VERSION 5.7 ;
BUSBITCHARS "[]" ;
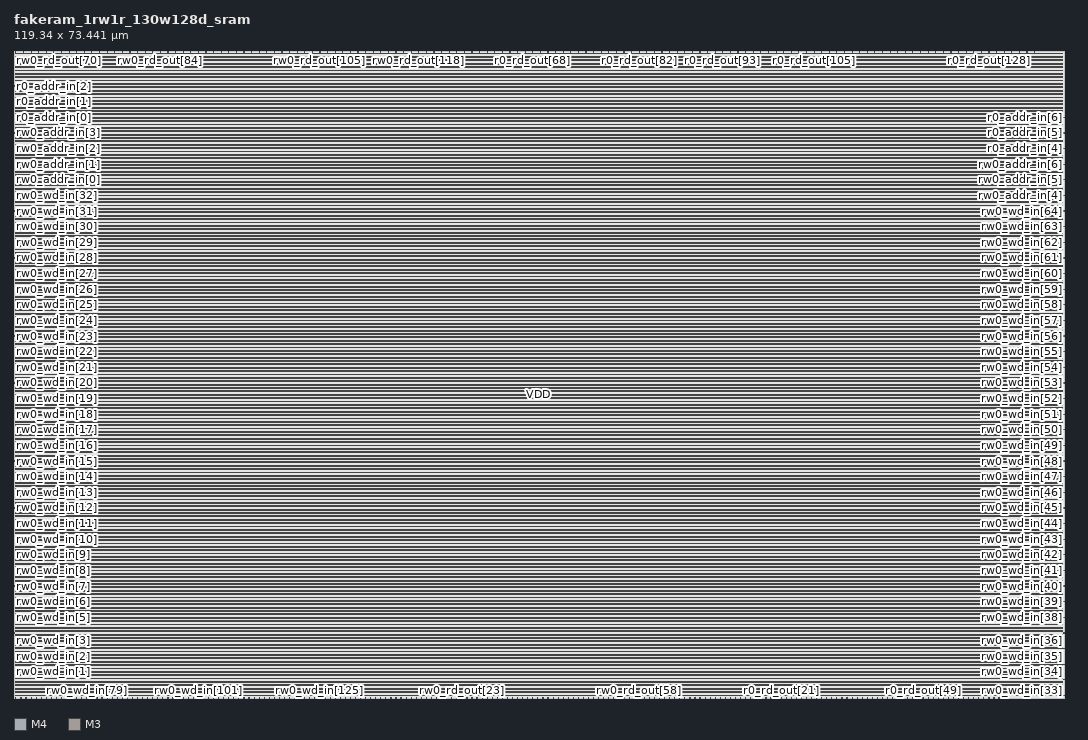
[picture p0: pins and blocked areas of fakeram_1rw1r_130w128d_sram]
MACRO fakeram_1rw1r_130w128d_sram
  FOREIGN fakeram_1rw1r_130w128d_sram 0 0 ;
  SYMMETRY X Y R90 ;
  SIZE 119.340 BY 73.441 ;
  CLASS BLOCK ;
  PIN rw0_wd_in[0]
    DIRECTION INPUT ;
    USE SIGNAL ;
    SHAPE ABUTMENT ;
    PORT
      LAYER M4 ;
      RECT 0.000 0.276 0.072 0.300 ;
    END
  END rw0_wd_in[0]
  PIN rw0_wd_in[1]
    DIRECTION INPUT ;
    USE SIGNAL ;
    SHAPE ABUTMENT ;
    PORT
      LAYER M4 ;
      RECT 0.000 2.052 0.072 2.076 ;
    END
  END rw0_wd_in[1]
  PIN rw0_wd_in[2]
    DIRECTION INPUT ;
    USE SIGNAL ;
    SHAPE ABUTMENT ;
    PORT
      LAYER M4 ;
      RECT 0.000 3.828 0.072 3.852 ;
    END
  END rw0_wd_in[2]
  PIN rw0_wd_in[3]
    DIRECTION INPUT ;
    USE SIGNAL ;
    SHAPE ABUTMENT ;
    PORT
      LAYER M4 ;
      RECT 0.000 5.604 0.072 5.628 ;
    END
  END rw0_wd_in[3]
  PIN rw0_wd_in[4]
    DIRECTION INPUT ;
    USE SIGNAL ;
    SHAPE ABUTMENT ;
    PORT
      LAYER M4 ;
      RECT 0.000 7.380 0.072 7.404 ;
    END
  END rw0_wd_in[4]
  PIN rw0_wd_in[5]
    DIRECTION INPUT ;
    USE SIGNAL ;
    SHAPE ABUTMENT ;
    PORT
      LAYER M4 ;
      RECT 0.000 9.156 0.072 9.180 ;
    END
  END rw0_wd_in[5]
  PIN rw0_wd_in[6]
    DIRECTION INPUT ;
    USE SIGNAL ;
    SHAPE ABUTMENT ;
    PORT
      LAYER M4 ;
      RECT 0.000 10.932 0.072 10.956 ;
    END
  END rw0_wd_in[6]
  PIN rw0_wd_in[7]
    DIRECTION INPUT ;
    USE SIGNAL ;
    SHAPE ABUTMENT ;
    PORT
      LAYER M4 ;
      RECT 0.000 12.708 0.072 12.732 ;
    END
  END rw0_wd_in[7]
  PIN rw0_wd_in[8]
    DIRECTION INPUT ;
    USE SIGNAL ;
    SHAPE ABUTMENT ;
    PORT
      LAYER M4 ;
      RECT 0.000 14.484 0.072 14.508 ;
    END
  END rw0_wd_in[8]
  PIN rw0_wd_in[9]
    DIRECTION INPUT ;
    USE SIGNAL ;
    SHAPE ABUTMENT ;
    PORT
      LAYER M4 ;
      RECT 0.000 16.260 0.072 16.284 ;
    END
  END rw0_wd_in[9]
  PIN rw0_wd_in[10]
    DIRECTION INPUT ;
    USE SIGNAL ;
    SHAPE ABUTMENT ;
    PORT
      LAYER M4 ;
      RECT 0.000 18.036 0.072 18.060 ;
    END
  END rw0_wd_in[10]
  PIN rw0_wd_in[11]
    DIRECTION INPUT ;
    USE SIGNAL ;
    SHAPE ABUTMENT ;
    PORT
      LAYER M4 ;
      RECT 0.000 19.812 0.072 19.836 ;
    END
  END rw0_wd_in[11]
  PIN rw0_wd_in[12]
    DIRECTION INPUT ;
    USE SIGNAL ;
    SHAPE ABUTMENT ;
    PORT
      LAYER M4 ;
      RECT 0.000 21.588 0.072 21.612 ;
    END
  END rw0_wd_in[12]
  PIN rw0_wd_in[13]
    DIRECTION INPUT ;
    USE SIGNAL ;
    SHAPE ABUTMENT ;
    PORT
      LAYER M4 ;
      RECT 0.000 23.364 0.072 23.388 ;
    END
  END rw0_wd_in[13]
  PIN rw0_wd_in[14]
    DIRECTION INPUT ;
    USE SIGNAL ;
    SHAPE ABUTMENT ;
    PORT
      LAYER M4 ;
      RECT 0.000 25.140 0.072 25.164 ;
    END
  END rw0_wd_in[14]
  PIN rw0_wd_in[15]
    DIRECTION INPUT ;
    USE SIGNAL ;
    SHAPE ABUTMENT ;
    PORT
      LAYER M4 ;
      RECT 0.000 26.916 0.072 26.940 ;
    END
  END rw0_wd_in[15]
  PIN rw0_wd_in[16]
    DIRECTION INPUT ;
    USE SIGNAL ;
    SHAPE ABUTMENT ;
    PORT
      LAYER M4 ;
      RECT 0.000 28.692 0.072 28.716 ;
    END
  END rw0_wd_in[16]
  PIN rw0_wd_in[17]
    DIRECTION INPUT ;
    USE SIGNAL ;
    SHAPE ABUTMENT ;
    PORT
      LAYER M4 ;
      RECT 0.000 30.468 0.072 30.492 ;
    END
  END rw0_wd_in[17]
  PIN rw0_wd_in[18]
    DIRECTION INPUT ;
    USE SIGNAL ;
    SHAPE ABUTMENT ;
    PORT
      LAYER M4 ;
      RECT 0.000 32.244 0.072 32.268 ;
    END
  END rw0_wd_in[18]
  PIN rw0_wd_in[19]
    DIRECTION INPUT ;
    USE SIGNAL ;
    SHAPE ABUTMENT ;
    PORT
      LAYER M4 ;
      RECT 0.000 34.020 0.072 34.044 ;
    END
  END rw0_wd_in[19]
  PIN rw0_wd_in[20]
    DIRECTION INPUT ;
    USE SIGNAL ;
    SHAPE ABUTMENT ;
    PORT
      LAYER M4 ;
      RECT 0.000 35.796 0.072 35.820 ;
    END
  END rw0_wd_in[20]
  PIN rw0_wd_in[21]
    DIRECTION INPUT ;
    USE SIGNAL ;
    SHAPE ABUTMENT ;
    PORT
      LAYER M4 ;
      RECT 0.000 37.572 0.072 37.596 ;
    END
  END rw0_wd_in[21]
  PIN rw0_wd_in[22]
    DIRECTION INPUT ;
    USE SIGNAL ;
    SHAPE ABUTMENT ;
    PORT
      LAYER M4 ;
      RECT 0.000 39.348 0.072 39.372 ;
    END
  END rw0_wd_in[22]
  PIN rw0_wd_in[23]
    DIRECTION INPUT ;
    USE SIGNAL ;
    SHAPE ABUTMENT ;
    PORT
      LAYER M4 ;
      RECT 0.000 41.124 0.072 41.148 ;
    END
  END rw0_wd_in[23]
  PIN rw0_wd_in[24]
    DIRECTION INPUT ;
    USE SIGNAL ;
    SHAPE ABUTMENT ;
    PORT
      LAYER M4 ;
      RECT 0.000 42.900 0.072 42.924 ;
    END
  END rw0_wd_in[24]
  PIN rw0_wd_in[25]
    DIRECTION INPUT ;
    USE SIGNAL ;
    SHAPE ABUTMENT ;
    PORT
      LAYER M4 ;
      RECT 0.000 44.676 0.072 44.700 ;
    END
  END rw0_wd_in[25]
  PIN rw0_wd_in[26]
    DIRECTION INPUT ;
    USE SIGNAL ;
    SHAPE ABUTMENT ;
    PORT
      LAYER M4 ;
      RECT 0.000 46.452 0.072 46.476 ;
    END
  END rw0_wd_in[26]
  PIN rw0_wd_in[27]
    DIRECTION INPUT ;
    USE SIGNAL ;
    SHAPE ABUTMENT ;
    PORT
      LAYER M4 ;
      RECT 0.000 48.228 0.072 48.252 ;
    END
  END rw0_wd_in[27]
  PIN rw0_wd_in[28]
    DIRECTION INPUT ;
    USE SIGNAL ;
    SHAPE ABUTMENT ;
    PORT
      LAYER M4 ;
      RECT 0.000 50.004 0.072 50.028 ;
    END
  END rw0_wd_in[28]
  PIN rw0_wd_in[29]
    DIRECTION INPUT ;
    USE SIGNAL ;
    SHAPE ABUTMENT ;
    PORT
      LAYER M4 ;
      RECT 0.000 51.780 0.072 51.804 ;
    END
  END rw0_wd_in[29]
  PIN rw0_wd_in[30]
    DIRECTION INPUT ;
    USE SIGNAL ;
    SHAPE ABUTMENT ;
    PORT
      LAYER M4 ;
      RECT 0.000 53.556 0.072 53.580 ;
    END
  END rw0_wd_in[30]
  PIN rw0_wd_in[31]
    DIRECTION INPUT ;
    USE SIGNAL ;
    SHAPE ABUTMENT ;
    PORT
      LAYER M4 ;
      RECT 0.000 55.332 0.072 55.356 ;
    END
  END rw0_wd_in[31]
  PIN rw0_wd_in[32]
    DIRECTION INPUT ;
    USE SIGNAL ;
    SHAPE ABUTMENT ;
    PORT
      LAYER M4 ;
      RECT 0.000 57.108 0.072 57.132 ;
    END
  END rw0_wd_in[32]
  PIN rw0_wd_in[33]
    DIRECTION INPUT ;
    USE SIGNAL ;
    SHAPE ABUTMENT ;
    PORT
      LAYER M4 ;
      RECT 119.268 0.276 119.340 0.300 ;
    END
  END rw0_wd_in[33]
  PIN rw0_wd_in[34]
    DIRECTION INPUT ;
    USE SIGNAL ;
    SHAPE ABUTMENT ;
    PORT
      LAYER M4 ;
      RECT 119.268 2.052 119.340 2.076 ;
    END
  END rw0_wd_in[34]
  PIN rw0_wd_in[35]
    DIRECTION INPUT ;
    USE SIGNAL ;
    SHAPE ABUTMENT ;
    PORT
      LAYER M4 ;
      RECT 119.268 3.828 119.340 3.852 ;
    END
  END rw0_wd_in[35]
  PIN rw0_wd_in[36]
    DIRECTION INPUT ;
    USE SIGNAL ;
    SHAPE ABUTMENT ;
    PORT
      LAYER M4 ;
      RECT 119.268 5.604 119.340 5.628 ;
    END
  END rw0_wd_in[36]
  PIN rw0_wd_in[37]
    DIRECTION INPUT ;
    USE SIGNAL ;
    SHAPE ABUTMENT ;
    PORT
      LAYER M4 ;
      RECT 119.268 7.380 119.340 7.404 ;
    END
  END rw0_wd_in[37]
  PIN rw0_wd_in[38]
    DIRECTION INPUT ;
    USE SIGNAL ;
    SHAPE ABUTMENT ;
    PORT
      LAYER M4 ;
      RECT 119.268 9.156 119.340 9.180 ;
    END
  END rw0_wd_in[38]
  PIN rw0_wd_in[39]
    DIRECTION INPUT ;
    USE SIGNAL ;
    SHAPE ABUTMENT ;
    PORT
      LAYER M4 ;
      RECT 119.268 10.932 119.340 10.956 ;
    END
  END rw0_wd_in[39]
  PIN rw0_wd_in[40]
    DIRECTION INPUT ;
    USE SIGNAL ;
    SHAPE ABUTMENT ;
    PORT
      LAYER M4 ;
      RECT 119.268 12.708 119.340 12.732 ;
    END
  END rw0_wd_in[40]
  PIN rw0_wd_in[41]
    DIRECTION INPUT ;
    USE SIGNAL ;
    SHAPE ABUTMENT ;
    PORT
      LAYER M4 ;
      RECT 119.268 14.484 119.340 14.508 ;
    END
  END rw0_wd_in[41]
  PIN rw0_wd_in[42]
    DIRECTION INPUT ;
    USE SIGNAL ;
    SHAPE ABUTMENT ;
    PORT
      LAYER M4 ;
      RECT 119.268 16.260 119.340 16.284 ;
    END
  END rw0_wd_in[42]
  PIN rw0_wd_in[43]
    DIRECTION INPUT ;
    USE SIGNAL ;
    SHAPE ABUTMENT ;
    PORT
      LAYER M4 ;
      RECT 119.268 18.036 119.340 18.060 ;
    END
  END rw0_wd_in[43]
  PIN rw0_wd_in[44]
    DIRECTION INPUT ;
    USE SIGNAL ;
    SHAPE ABUTMENT ;
    PORT
      LAYER M4 ;
      RECT 119.268 19.812 119.340 19.836 ;
    END
  END rw0_wd_in[44]
  PIN rw0_wd_in[45]
    DIRECTION INPUT ;
    USE SIGNAL ;
    SHAPE ABUTMENT ;
    PORT
      LAYER M4 ;
      RECT 119.268 21.588 119.340 21.612 ;
    END
  END rw0_wd_in[45]
  PIN rw0_wd_in[46]
    DIRECTION INPUT ;
    USE SIGNAL ;
    SHAPE ABUTMENT ;
    PORT
      LAYER M4 ;
      RECT 119.268 23.364 119.340 23.388 ;
    END
  END rw0_wd_in[46]
  PIN rw0_wd_in[47]
    DIRECTION INPUT ;
    USE SIGNAL ;
    SHAPE ABUTMENT ;
    PORT
      LAYER M4 ;
      RECT 119.268 25.140 119.340 25.164 ;
    END
  END rw0_wd_in[47]
  PIN rw0_wd_in[48]
    DIRECTION INPUT ;
    USE SIGNAL ;
    SHAPE ABUTMENT ;
    PORT
      LAYER M4 ;
      RECT 119.268 26.916 119.340 26.940 ;
    END
  END rw0_wd_in[48]
  PIN rw0_wd_in[49]
    DIRECTION INPUT ;
    USE SIGNAL ;
    SHAPE ABUTMENT ;
    PORT
      LAYER M4 ;
      RECT 119.268 28.692 119.340 28.716 ;
    END
  END rw0_wd_in[49]
  PIN rw0_wd_in[50]
    DIRECTION INPUT ;
    USE SIGNAL ;
    SHAPE ABUTMENT ;
    PORT
      LAYER M4 ;
      RECT 119.268 30.468 119.340 30.492 ;
    END
  END rw0_wd_in[50]
  PIN rw0_wd_in[51]
    DIRECTION INPUT ;
    USE SIGNAL ;
    SHAPE ABUTMENT ;
    PORT
      LAYER M4 ;
      RECT 119.268 32.244 119.340 32.268 ;
    END
  END rw0_wd_in[51]
  PIN rw0_wd_in[52]
    DIRECTION INPUT ;
    USE SIGNAL ;
    SHAPE ABUTMENT ;
    PORT
      LAYER M4 ;
      RECT 119.268 34.020 119.340 34.044 ;
    END
  END rw0_wd_in[52]
  PIN rw0_wd_in[53]
    DIRECTION INPUT ;
    USE SIGNAL ;
    SHAPE ABUTMENT ;
    PORT
      LAYER M4 ;
      RECT 119.268 35.796 119.340 35.820 ;
    END
  END rw0_wd_in[53]
  PIN rw0_wd_in[54]
    DIRECTION INPUT ;
    USE SIGNAL ;
    SHAPE ABUTMENT ;
    PORT
      LAYER M4 ;
      RECT 119.268 37.572 119.340 37.596 ;
    END
  END rw0_wd_in[54]
  PIN rw0_wd_in[55]
    DIRECTION INPUT ;
    USE SIGNAL ;
    SHAPE ABUTMENT ;
    PORT
      LAYER M4 ;
      RECT 119.268 39.348 119.340 39.372 ;
    END
  END rw0_wd_in[55]
  PIN rw0_wd_in[56]
    DIRECTION INPUT ;
    USE SIGNAL ;
    SHAPE ABUTMENT ;
    PORT
      LAYER M4 ;
      RECT 119.268 41.124 119.340 41.148 ;
    END
  END rw0_wd_in[56]
  PIN rw0_wd_in[57]
    DIRECTION INPUT ;
    USE SIGNAL ;
    SHAPE ABUTMENT ;
    PORT
      LAYER M4 ;
      RECT 119.268 42.900 119.340 42.924 ;
    END
  END rw0_wd_in[57]
  PIN rw0_wd_in[58]
    DIRECTION INPUT ;
    USE SIGNAL ;
    SHAPE ABUTMENT ;
    PORT
      LAYER M4 ;
      RECT 119.268 44.676 119.340 44.700 ;
    END
  END rw0_wd_in[58]
  PIN rw0_wd_in[59]
    DIRECTION INPUT ;
    USE SIGNAL ;
    SHAPE ABUTMENT ;
    PORT
      LAYER M4 ;
      RECT 119.268 46.452 119.340 46.476 ;
    END
  END rw0_wd_in[59]
  PIN rw0_wd_in[60]
    DIRECTION INPUT ;
    USE SIGNAL ;
    SHAPE ABUTMENT ;
    PORT
      LAYER M4 ;
      RECT 119.268 48.228 119.340 48.252 ;
    END
  END rw0_wd_in[60]
  PIN rw0_wd_in[61]
    DIRECTION INPUT ;
    USE SIGNAL ;
    SHAPE ABUTMENT ;
    PORT
      LAYER M4 ;
      RECT 119.268 50.004 119.340 50.028 ;
    END
  END rw0_wd_in[61]
  PIN rw0_wd_in[62]
    DIRECTION INPUT ;
    USE SIGNAL ;
    SHAPE ABUTMENT ;
    PORT
      LAYER M4 ;
      RECT 119.268 51.780 119.340 51.804 ;
    END
  END rw0_wd_in[62]
  PIN rw0_wd_in[63]
    DIRECTION INPUT ;
    USE SIGNAL ;
    SHAPE ABUTMENT ;
    PORT
      LAYER M4 ;
      RECT 119.268 53.556 119.340 53.580 ;
    END
  END rw0_wd_in[63]
  PIN rw0_wd_in[64]
    DIRECTION INPUT ;
    USE SIGNAL ;
    SHAPE ABUTMENT ;
    PORT
      LAYER M4 ;
      RECT 119.268 55.332 119.340 55.356 ;
    END
  END rw0_wd_in[64]
  PIN rw0_wd_in[65]
    DIRECTION INPUT ;
    USE SIGNAL ;
    SHAPE ABUTMENT ;
    PORT
      LAYER M3 ;
      RECT 0.207 0.000 0.225 0.054 ;
    END
  END rw0_wd_in[65]
  PIN rw0_wd_in[66]
    DIRECTION INPUT ;
    USE SIGNAL ;
    SHAPE ABUTMENT ;
    PORT
      LAYER M3 ;
      RECT 0.783 0.000 0.801 0.054 ;
    END
  END rw0_wd_in[66]
  PIN rw0_wd_in[67]
    DIRECTION INPUT ;
    USE SIGNAL ;
    SHAPE ABUTMENT ;
    PORT
      LAYER M3 ;
      RECT 1.359 0.000 1.377 0.054 ;
    END
  END rw0_wd_in[67]
  PIN rw0_wd_in[68]
    DIRECTION INPUT ;
    USE SIGNAL ;
    SHAPE ABUTMENT ;
    PORT
      LAYER M3 ;
      RECT 1.935 0.000 1.953 0.054 ;
    END
  END rw0_wd_in[68]
  PIN rw0_wd_in[69]
    DIRECTION INPUT ;
    USE SIGNAL ;
    SHAPE ABUTMENT ;
    PORT
      LAYER M3 ;
      RECT 2.511 0.000 2.529 0.054 ;
    END
  END rw0_wd_in[69]
  PIN rw0_wd_in[70]
    DIRECTION INPUT ;
    USE SIGNAL ;
    SHAPE ABUTMENT ;
    PORT
      LAYER M3 ;
      RECT 3.087 0.000 3.105 0.054 ;
    END
  END rw0_wd_in[70]
  PIN rw0_wd_in[71]
    DIRECTION INPUT ;
    USE SIGNAL ;
    SHAPE ABUTMENT ;
    PORT
      LAYER M3 ;
      RECT 3.663 0.000 3.681 0.054 ;
    END
  END rw0_wd_in[71]
  PIN rw0_wd_in[72]
    DIRECTION INPUT ;
    USE SIGNAL ;
    SHAPE ABUTMENT ;
    PORT
      LAYER M3 ;
      RECT 4.239 0.000 4.257 0.054 ;
    END
  END rw0_wd_in[72]
  PIN rw0_wd_in[73]
    DIRECTION INPUT ;
    USE SIGNAL ;
    SHAPE ABUTMENT ;
    PORT
      LAYER M3 ;
      RECT 4.815 0.000 4.833 0.054 ;
    END
  END rw0_wd_in[73]
  PIN rw0_wd_in[74]
    DIRECTION INPUT ;
    USE SIGNAL ;
    SHAPE ABUTMENT ;
    PORT
      LAYER M3 ;
      RECT 5.391 0.000 5.409 0.054 ;
    END
  END rw0_wd_in[74]
  PIN rw0_wd_in[75]
    DIRECTION INPUT ;
    USE SIGNAL ;
    SHAPE ABUTMENT ;
    PORT
      LAYER M3 ;
      RECT 5.967 0.000 5.985 0.054 ;
    END
  END rw0_wd_in[75]
  PIN rw0_wd_in[76]
    DIRECTION INPUT ;
    USE SIGNAL ;
    SHAPE ABUTMENT ;
    PORT
      LAYER M3 ;
      RECT 6.543 0.000 6.561 0.054 ;
    END
  END rw0_wd_in[76]
  PIN rw0_wd_in[77]
    DIRECTION INPUT ;
    USE SIGNAL ;
    SHAPE ABUTMENT ;
    PORT
      LAYER M3 ;
      RECT 7.119 0.000 7.137 0.054 ;
    END
  END rw0_wd_in[77]
  PIN rw0_wd_in[78]
    DIRECTION INPUT ;
    USE SIGNAL ;
    SHAPE ABUTMENT ;
    PORT
      LAYER M3 ;
      RECT 7.695 0.000 7.713 0.054 ;
    END
  END rw0_wd_in[78]
  PIN rw0_wd_in[79]
    DIRECTION INPUT ;
    USE SIGNAL ;
    SHAPE ABUTMENT ;
    PORT
      LAYER M3 ;
      RECT 8.271 0.000 8.289 0.054 ;
    END
  END rw0_wd_in[79]
  PIN rw0_wd_in[80]
    DIRECTION INPUT ;
    USE SIGNAL ;
    SHAPE ABUTMENT ;
    PORT
      LAYER M3 ;
      RECT 8.847 0.000 8.865 0.054 ;
    END
  END rw0_wd_in[80]
  PIN rw0_wd_in[81]
    DIRECTION INPUT ;
    USE SIGNAL ;
    SHAPE ABUTMENT ;
    PORT
      LAYER M3 ;
      RECT 9.423 0.000 9.441 0.054 ;
    END
  END rw0_wd_in[81]
  PIN rw0_wd_in[82]
    DIRECTION INPUT ;
    USE SIGNAL ;
    SHAPE ABUTMENT ;
    PORT
      LAYER M3 ;
      RECT 9.999 0.000 10.017 0.054 ;
    END
  END rw0_wd_in[82]
  PIN rw0_wd_in[83]
    DIRECTION INPUT ;
    USE SIGNAL ;
    SHAPE ABUTMENT ;
    PORT
      LAYER M3 ;
      RECT 10.575 0.000 10.593 0.054 ;
    END
  END rw0_wd_in[83]
  PIN rw0_wd_in[84]
    DIRECTION INPUT ;
    USE SIGNAL ;
    SHAPE ABUTMENT ;
    PORT
      LAYER M3 ;
      RECT 11.151 0.000 11.169 0.054 ;
    END
  END rw0_wd_in[84]
  PIN rw0_wd_in[85]
    DIRECTION INPUT ;
    USE SIGNAL ;
    SHAPE ABUTMENT ;
    PORT
      LAYER M3 ;
      RECT 11.727 0.000 11.745 0.054 ;
    END
  END rw0_wd_in[85]
  PIN rw0_wd_in[86]
    DIRECTION INPUT ;
    USE SIGNAL ;
    SHAPE ABUTMENT ;
    PORT
      LAYER M3 ;
      RECT 12.303 0.000 12.321 0.054 ;
    END
  END rw0_wd_in[86]
  PIN rw0_wd_in[87]
    DIRECTION INPUT ;
    USE SIGNAL ;
    SHAPE ABUTMENT ;
    PORT
      LAYER M3 ;
      RECT 12.879 0.000 12.897 0.054 ;
    END
  END rw0_wd_in[87]
  PIN rw0_wd_in[88]
    DIRECTION INPUT ;
    USE SIGNAL ;
    SHAPE ABUTMENT ;
    PORT
      LAYER M3 ;
      RECT 13.455 0.000 13.473 0.054 ;
    END
  END rw0_wd_in[88]
  PIN rw0_wd_in[89]
    DIRECTION INPUT ;
    USE SIGNAL ;
    SHAPE ABUTMENT ;
    PORT
      LAYER M3 ;
      RECT 14.031 0.000 14.049 0.054 ;
    END
  END rw0_wd_in[89]
  PIN rw0_wd_in[90]
    DIRECTION INPUT ;
    USE SIGNAL ;
    SHAPE ABUTMENT ;
    PORT
      LAYER M3 ;
      RECT 14.607 0.000 14.625 0.054 ;
    END
  END rw0_wd_in[90]
  PIN rw0_wd_in[91]
    DIRECTION INPUT ;
    USE SIGNAL ;
    SHAPE ABUTMENT ;
    PORT
      LAYER M3 ;
      RECT 15.183 0.000 15.201 0.054 ;
    END
  END rw0_wd_in[91]
  PIN rw0_wd_in[92]
    DIRECTION INPUT ;
    USE SIGNAL ;
    SHAPE ABUTMENT ;
    PORT
      LAYER M3 ;
      RECT 15.759 0.000 15.777 0.054 ;
    END
  END rw0_wd_in[92]
  PIN rw0_wd_in[93]
    DIRECTION INPUT ;
    USE SIGNAL ;
    SHAPE ABUTMENT ;
    PORT
      LAYER M3 ;
      RECT 16.335 0.000 16.353 0.054 ;
    END
  END rw0_wd_in[93]
  PIN rw0_wd_in[94]
    DIRECTION INPUT ;
    USE SIGNAL ;
    SHAPE ABUTMENT ;
    PORT
      LAYER M3 ;
      RECT 16.911 0.000 16.929 0.054 ;
    END
  END rw0_wd_in[94]
  PIN rw0_wd_in[95]
    DIRECTION INPUT ;
    USE SIGNAL ;
    SHAPE ABUTMENT ;
    PORT
      LAYER M3 ;
      RECT 17.487 0.000 17.505 0.054 ;
    END
  END rw0_wd_in[95]
  PIN rw0_wd_in[96]
    DIRECTION INPUT ;
    USE SIGNAL ;
    SHAPE ABUTMENT ;
    PORT
      LAYER M3 ;
      RECT 18.063 0.000 18.081 0.054 ;
    END
  END rw0_wd_in[96]
  PIN rw0_wd_in[97]
    DIRECTION INPUT ;
    USE SIGNAL ;
    SHAPE ABUTMENT ;
    PORT
      LAYER M3 ;
      RECT 18.639 0.000 18.657 0.054 ;
    END
  END rw0_wd_in[97]
  PIN rw0_wd_in[98]
    DIRECTION INPUT ;
    USE SIGNAL ;
    SHAPE ABUTMENT ;
    PORT
      LAYER M3 ;
      RECT 19.215 0.000 19.233 0.054 ;
    END
  END rw0_wd_in[98]
  PIN rw0_wd_in[99]
    DIRECTION INPUT ;
    USE SIGNAL ;
    SHAPE ABUTMENT ;
    PORT
      LAYER M3 ;
      RECT 19.791 0.000 19.809 0.054 ;
    END
  END rw0_wd_in[99]
  PIN rw0_wd_in[100]
    DIRECTION INPUT ;
    USE SIGNAL ;
    SHAPE ABUTMENT ;
    PORT
      LAYER M3 ;
      RECT 20.367 0.000 20.385 0.054 ;
    END
  END rw0_wd_in[100]
  PIN rw0_wd_in[101]
    DIRECTION INPUT ;
    USE SIGNAL ;
    SHAPE ABUTMENT ;
    PORT
      LAYER M3 ;
      RECT 20.943 0.000 20.961 0.054 ;
    END
  END rw0_wd_in[101]
  PIN rw0_wd_in[102]
    DIRECTION INPUT ;
    USE SIGNAL ;
    SHAPE ABUTMENT ;
    PORT
      LAYER M3 ;
      RECT 21.519 0.000 21.537 0.054 ;
    END
  END rw0_wd_in[102]
  PIN rw0_wd_in[103]
    DIRECTION INPUT ;
    USE SIGNAL ;
    SHAPE ABUTMENT ;
    PORT
      LAYER M3 ;
      RECT 22.095 0.000 22.113 0.054 ;
    END
  END rw0_wd_in[103]
  PIN rw0_wd_in[104]
    DIRECTION INPUT ;
    USE SIGNAL ;
    SHAPE ABUTMENT ;
    PORT
      LAYER M3 ;
      RECT 22.671 0.000 22.689 0.054 ;
    END
  END rw0_wd_in[104]
  PIN rw0_wd_in[105]
    DIRECTION INPUT ;
    USE SIGNAL ;
    SHAPE ABUTMENT ;
    PORT
      LAYER M3 ;
      RECT 23.247 0.000 23.265 0.054 ;
    END
  END rw0_wd_in[105]
  PIN rw0_wd_in[106]
    DIRECTION INPUT ;
    USE SIGNAL ;
    SHAPE ABUTMENT ;
    PORT
      LAYER M3 ;
      RECT 23.823 0.000 23.841 0.054 ;
    END
  END rw0_wd_in[106]
  PIN rw0_wd_in[107]
    DIRECTION INPUT ;
    USE SIGNAL ;
    SHAPE ABUTMENT ;
    PORT
      LAYER M3 ;
      RECT 24.399 0.000 24.417 0.054 ;
    END
  END rw0_wd_in[107]
  PIN rw0_wd_in[108]
    DIRECTION INPUT ;
    USE SIGNAL ;
    SHAPE ABUTMENT ;
    PORT
      LAYER M3 ;
      RECT 24.975 0.000 24.993 0.054 ;
    END
  END rw0_wd_in[108]
  PIN rw0_wd_in[109]
    DIRECTION INPUT ;
    USE SIGNAL ;
    SHAPE ABUTMENT ;
    PORT
      LAYER M3 ;
      RECT 25.551 0.000 25.569 0.054 ;
    END
  END rw0_wd_in[109]
  PIN rw0_wd_in[110]
    DIRECTION INPUT ;
    USE SIGNAL ;
    SHAPE ABUTMENT ;
    PORT
      LAYER M3 ;
      RECT 26.127 0.000 26.145 0.054 ;
    END
  END rw0_wd_in[110]
  PIN rw0_wd_in[111]
    DIRECTION INPUT ;
    USE SIGNAL ;
    SHAPE ABUTMENT ;
    PORT
      LAYER M3 ;
      RECT 26.703 0.000 26.721 0.054 ;
    END
  END rw0_wd_in[111]
  PIN rw0_wd_in[112]
    DIRECTION INPUT ;
    USE SIGNAL ;
    SHAPE ABUTMENT ;
    PORT
      LAYER M3 ;
      RECT 27.279 0.000 27.297 0.054 ;
    END
  END rw0_wd_in[112]
  PIN rw0_wd_in[113]
    DIRECTION INPUT ;
    USE SIGNAL ;
    SHAPE ABUTMENT ;
    PORT
      LAYER M3 ;
      RECT 27.855 0.000 27.873 0.054 ;
    END
  END rw0_wd_in[113]
  PIN rw0_wd_in[114]
    DIRECTION INPUT ;
    USE SIGNAL ;
    SHAPE ABUTMENT ;
    PORT
      LAYER M3 ;
      RECT 28.431 0.000 28.449 0.054 ;
    END
  END rw0_wd_in[114]
  PIN rw0_wd_in[115]
    DIRECTION INPUT ;
    USE SIGNAL ;
    SHAPE ABUTMENT ;
    PORT
      LAYER M3 ;
      RECT 29.007 0.000 29.025 0.054 ;
    END
  END rw0_wd_in[115]
  PIN rw0_wd_in[116]
    DIRECTION INPUT ;
    USE SIGNAL ;
    SHAPE ABUTMENT ;
    PORT
      LAYER M3 ;
      RECT 29.583 0.000 29.601 0.054 ;
    END
  END rw0_wd_in[116]
  PIN rw0_wd_in[117]
    DIRECTION INPUT ;
    USE SIGNAL ;
    SHAPE ABUTMENT ;
    PORT
      LAYER M3 ;
      RECT 30.159 0.000 30.177 0.054 ;
    END
  END rw0_wd_in[117]
  PIN rw0_wd_in[118]
    DIRECTION INPUT ;
    USE SIGNAL ;
    SHAPE ABUTMENT ;
    PORT
      LAYER M3 ;
      RECT 30.735 0.000 30.753 0.054 ;
    END
  END rw0_wd_in[118]
  PIN rw0_wd_in[119]
    DIRECTION INPUT ;
    USE SIGNAL ;
    SHAPE ABUTMENT ;
    PORT
      LAYER M3 ;
      RECT 31.311 0.000 31.329 0.054 ;
    END
  END rw0_wd_in[119]
  PIN rw0_wd_in[120]
    DIRECTION INPUT ;
    USE SIGNAL ;
    SHAPE ABUTMENT ;
    PORT
      LAYER M3 ;
      RECT 31.887 0.000 31.905 0.054 ;
    END
  END rw0_wd_in[120]
  PIN rw0_wd_in[121]
    DIRECTION INPUT ;
    USE SIGNAL ;
    SHAPE ABUTMENT ;
    PORT
      LAYER M3 ;
      RECT 32.463 0.000 32.481 0.054 ;
    END
  END rw0_wd_in[121]
  PIN rw0_wd_in[122]
    DIRECTION INPUT ;
    USE SIGNAL ;
    SHAPE ABUTMENT ;
    PORT
      LAYER M3 ;
      RECT 33.039 0.000 33.057 0.054 ;
    END
  END rw0_wd_in[122]
  PIN rw0_wd_in[123]
    DIRECTION INPUT ;
    USE SIGNAL ;
    SHAPE ABUTMENT ;
    PORT
      LAYER M3 ;
      RECT 33.615 0.000 33.633 0.054 ;
    END
  END rw0_wd_in[123]
  PIN rw0_wd_in[124]
    DIRECTION INPUT ;
    USE SIGNAL ;
    SHAPE ABUTMENT ;
    PORT
      LAYER M3 ;
      RECT 34.191 0.000 34.209 0.054 ;
    END
  END rw0_wd_in[124]
  PIN rw0_wd_in[125]
    DIRECTION INPUT ;
    USE SIGNAL ;
    SHAPE ABUTMENT ;
    PORT
      LAYER M3 ;
      RECT 34.767 0.000 34.785 0.054 ;
    END
  END rw0_wd_in[125]
  PIN rw0_wd_in[126]
    DIRECTION INPUT ;
    USE SIGNAL ;
    SHAPE ABUTMENT ;
    PORT
      LAYER M3 ;
      RECT 35.343 0.000 35.361 0.054 ;
    END
  END rw0_wd_in[126]
  PIN rw0_wd_in[127]
    DIRECTION INPUT ;
    USE SIGNAL ;
    SHAPE ABUTMENT ;
    PORT
      LAYER M3 ;
      RECT 35.919 0.000 35.937 0.054 ;
    END
  END rw0_wd_in[127]
  PIN rw0_wd_in[128]
    DIRECTION INPUT ;
    USE SIGNAL ;
    SHAPE ABUTMENT ;
    PORT
      LAYER M3 ;
      RECT 36.495 0.000 36.513 0.054 ;
    END
  END rw0_wd_in[128]
  PIN rw0_wd_in[129]
    DIRECTION INPUT ;
    USE SIGNAL ;
    SHAPE ABUTMENT ;
    PORT
      LAYER M3 ;
      RECT 37.071 0.000 37.089 0.054 ;
    END
  END rw0_wd_in[129]
  PIN rw0_rd_out[0]
    DIRECTION OUTPUT ;
    USE SIGNAL ;
    SHAPE ABUTMENT ;
    PORT
      LAYER M3 ;
      RECT 37.647 0.000 37.665 0.054 ;
    END
  END rw0_rd_out[0]
  PIN rw0_rd_out[1]
    DIRECTION OUTPUT ;
    USE SIGNAL ;
    SHAPE ABUTMENT ;
    PORT
      LAYER M3 ;
      RECT 38.223 0.000 38.241 0.054 ;
    END
  END rw0_rd_out[1]
  PIN rw0_rd_out[2]
    DIRECTION OUTPUT ;
    USE SIGNAL ;
    SHAPE ABUTMENT ;
    PORT
      LAYER M3 ;
      RECT 38.799 0.000 38.817 0.054 ;
    END
  END rw0_rd_out[2]
  PIN rw0_rd_out[3]
    DIRECTION OUTPUT ;
    USE SIGNAL ;
    SHAPE ABUTMENT ;
    PORT
      LAYER M3 ;
      RECT 39.375 0.000 39.393 0.054 ;
    END
  END rw0_rd_out[3]
  PIN rw0_rd_out[4]
    DIRECTION OUTPUT ;
    USE SIGNAL ;
    SHAPE ABUTMENT ;
    PORT
      LAYER M3 ;
      RECT 39.951 0.000 39.969 0.054 ;
    END
  END rw0_rd_out[4]
  PIN rw0_rd_out[5]
    DIRECTION OUTPUT ;
    USE SIGNAL ;
    SHAPE ABUTMENT ;
    PORT
      LAYER M3 ;
      RECT 40.527 0.000 40.545 0.054 ;
    END
  END rw0_rd_out[5]
  PIN rw0_rd_out[6]
    DIRECTION OUTPUT ;
    USE SIGNAL ;
    SHAPE ABUTMENT ;
    PORT
      LAYER M3 ;
      RECT 41.103 0.000 41.121 0.054 ;
    END
  END rw0_rd_out[6]
  PIN rw0_rd_out[7]
    DIRECTION OUTPUT ;
    USE SIGNAL ;
    SHAPE ABUTMENT ;
    PORT
      LAYER M3 ;
      RECT 41.679 0.000 41.697 0.054 ;
    END
  END rw0_rd_out[7]
  PIN rw0_rd_out[8]
    DIRECTION OUTPUT ;
    USE SIGNAL ;
    SHAPE ABUTMENT ;
    PORT
      LAYER M3 ;
      RECT 42.255 0.000 42.273 0.054 ;
    END
  END rw0_rd_out[8]
  PIN rw0_rd_out[9]
    DIRECTION OUTPUT ;
    USE SIGNAL ;
    SHAPE ABUTMENT ;
    PORT
      LAYER M3 ;
      RECT 42.831 0.000 42.849 0.054 ;
    END
  END rw0_rd_out[9]
  PIN rw0_rd_out[10]
    DIRECTION OUTPUT ;
    USE SIGNAL ;
    SHAPE ABUTMENT ;
    PORT
      LAYER M3 ;
      RECT 43.407 0.000 43.425 0.054 ;
    END
  END rw0_rd_out[10]
  PIN rw0_rd_out[11]
    DIRECTION OUTPUT ;
    USE SIGNAL ;
    SHAPE ABUTMENT ;
    PORT
      LAYER M3 ;
      RECT 43.983 0.000 44.001 0.054 ;
    END
  END rw0_rd_out[11]
  PIN rw0_rd_out[12]
    DIRECTION OUTPUT ;
    USE SIGNAL ;
    SHAPE ABUTMENT ;
    PORT
      LAYER M3 ;
      RECT 44.559 0.000 44.577 0.054 ;
    END
  END rw0_rd_out[12]
  PIN rw0_rd_out[13]
    DIRECTION OUTPUT ;
    USE SIGNAL ;
    SHAPE ABUTMENT ;
    PORT
      LAYER M3 ;
      RECT 45.135 0.000 45.153 0.054 ;
    END
  END rw0_rd_out[13]
  PIN rw0_rd_out[14]
    DIRECTION OUTPUT ;
    USE SIGNAL ;
    SHAPE ABUTMENT ;
    PORT
      LAYER M3 ;
      RECT 45.711 0.000 45.729 0.054 ;
    END
  END rw0_rd_out[14]
  PIN rw0_rd_out[15]
    DIRECTION OUTPUT ;
    USE SIGNAL ;
    SHAPE ABUTMENT ;
    PORT
      LAYER M3 ;
      RECT 46.287 0.000 46.305 0.054 ;
    END
  END rw0_rd_out[15]
  PIN rw0_rd_out[16]
    DIRECTION OUTPUT ;
    USE SIGNAL ;
    SHAPE ABUTMENT ;
    PORT
      LAYER M3 ;
      RECT 46.863 0.000 46.881 0.054 ;
    END
  END rw0_rd_out[16]
  PIN rw0_rd_out[17]
    DIRECTION OUTPUT ;
    USE SIGNAL ;
    SHAPE ABUTMENT ;
    PORT
      LAYER M3 ;
      RECT 47.439 0.000 47.457 0.054 ;
    END
  END rw0_rd_out[17]
  PIN rw0_rd_out[18]
    DIRECTION OUTPUT ;
    USE SIGNAL ;
    SHAPE ABUTMENT ;
    PORT
      LAYER M3 ;
      RECT 48.015 0.000 48.033 0.054 ;
    END
  END rw0_rd_out[18]
  PIN rw0_rd_out[19]
    DIRECTION OUTPUT ;
    USE SIGNAL ;
    SHAPE ABUTMENT ;
    PORT
      LAYER M3 ;
      RECT 48.591 0.000 48.609 0.054 ;
    END
  END rw0_rd_out[19]
  PIN rw0_rd_out[20]
    DIRECTION OUTPUT ;
    USE SIGNAL ;
    SHAPE ABUTMENT ;
    PORT
      LAYER M3 ;
      RECT 49.167 0.000 49.185 0.054 ;
    END
  END rw0_rd_out[20]
  PIN rw0_rd_out[21]
    DIRECTION OUTPUT ;
    USE SIGNAL ;
    SHAPE ABUTMENT ;
    PORT
      LAYER M3 ;
      RECT 49.743 0.000 49.761 0.054 ;
    END
  END rw0_rd_out[21]
  PIN rw0_rd_out[22]
    DIRECTION OUTPUT ;
    USE SIGNAL ;
    SHAPE ABUTMENT ;
    PORT
      LAYER M3 ;
      RECT 50.319 0.000 50.337 0.054 ;
    END
  END rw0_rd_out[22]
  PIN rw0_rd_out[23]
    DIRECTION OUTPUT ;
    USE SIGNAL ;
    SHAPE ABUTMENT ;
    PORT
      LAYER M3 ;
      RECT 50.895 0.000 50.913 0.054 ;
    END
  END rw0_rd_out[23]
  PIN rw0_rd_out[24]
    DIRECTION OUTPUT ;
    USE SIGNAL ;
    SHAPE ABUTMENT ;
    PORT
      LAYER M3 ;
      RECT 51.471 0.000 51.489 0.054 ;
    END
  END rw0_rd_out[24]
  PIN rw0_rd_out[25]
    DIRECTION OUTPUT ;
    USE SIGNAL ;
    SHAPE ABUTMENT ;
    PORT
      LAYER M3 ;
      RECT 52.047 0.000 52.065 0.054 ;
    END
  END rw0_rd_out[25]
  PIN rw0_rd_out[26]
    DIRECTION OUTPUT ;
    USE SIGNAL ;
    SHAPE ABUTMENT ;
    PORT
      LAYER M3 ;
      RECT 52.623 0.000 52.641 0.054 ;
    END
  END rw0_rd_out[26]
  PIN rw0_rd_out[27]
    DIRECTION OUTPUT ;
    USE SIGNAL ;
    SHAPE ABUTMENT ;
    PORT
      LAYER M3 ;
      RECT 53.199 0.000 53.217 0.054 ;
    END
  END rw0_rd_out[27]
  PIN rw0_rd_out[28]
    DIRECTION OUTPUT ;
    USE SIGNAL ;
    SHAPE ABUTMENT ;
    PORT
      LAYER M3 ;
      RECT 53.775 0.000 53.793 0.054 ;
    END
  END rw0_rd_out[28]
  PIN rw0_rd_out[29]
    DIRECTION OUTPUT ;
    USE SIGNAL ;
    SHAPE ABUTMENT ;
    PORT
      LAYER M3 ;
      RECT 54.351 0.000 54.369 0.054 ;
    END
  END rw0_rd_out[29]
  PIN rw0_rd_out[30]
    DIRECTION OUTPUT ;
    USE SIGNAL ;
    SHAPE ABUTMENT ;
    PORT
      LAYER M3 ;
      RECT 54.927 0.000 54.945 0.054 ;
    END
  END rw0_rd_out[30]
  PIN rw0_rd_out[31]
    DIRECTION OUTPUT ;
    USE SIGNAL ;
    SHAPE ABUTMENT ;
    PORT
      LAYER M3 ;
      RECT 55.503 0.000 55.521 0.054 ;
    END
  END rw0_rd_out[31]
  PIN rw0_rd_out[32]
    DIRECTION OUTPUT ;
    USE SIGNAL ;
    SHAPE ABUTMENT ;
    PORT
      LAYER M3 ;
      RECT 56.079 0.000 56.097 0.054 ;
    END
  END rw0_rd_out[32]
  PIN rw0_rd_out[33]
    DIRECTION OUTPUT ;
    USE SIGNAL ;
    SHAPE ABUTMENT ;
    PORT
      LAYER M3 ;
      RECT 56.655 0.000 56.673 0.054 ;
    END
  END rw0_rd_out[33]
  PIN rw0_rd_out[34]
    DIRECTION OUTPUT ;
    USE SIGNAL ;
    SHAPE ABUTMENT ;
    PORT
      LAYER M3 ;
      RECT 57.231 0.000 57.249 0.054 ;
    END
  END rw0_rd_out[34]
  PIN rw0_rd_out[35]
    DIRECTION OUTPUT ;
    USE SIGNAL ;
    SHAPE ABUTMENT ;
    PORT
      LAYER M3 ;
      RECT 57.807 0.000 57.825 0.054 ;
    END
  END rw0_rd_out[35]
  PIN rw0_rd_out[36]
    DIRECTION OUTPUT ;
    USE SIGNAL ;
    SHAPE ABUTMENT ;
    PORT
      LAYER M3 ;
      RECT 58.383 0.000 58.401 0.054 ;
    END
  END rw0_rd_out[36]
  PIN rw0_rd_out[37]
    DIRECTION OUTPUT ;
    USE SIGNAL ;
    SHAPE ABUTMENT ;
    PORT
      LAYER M3 ;
      RECT 58.959 0.000 58.977 0.054 ;
    END
  END rw0_rd_out[37]
  PIN rw0_rd_out[38]
    DIRECTION OUTPUT ;
    USE SIGNAL ;
    SHAPE ABUTMENT ;
    PORT
      LAYER M3 ;
      RECT 59.535 0.000 59.553 0.054 ;
    END
  END rw0_rd_out[38]
  PIN rw0_rd_out[39]
    DIRECTION OUTPUT ;
    USE SIGNAL ;
    SHAPE ABUTMENT ;
    PORT
      LAYER M3 ;
      RECT 60.111 0.000 60.129 0.054 ;
    END
  END rw0_rd_out[39]
  PIN rw0_rd_out[40]
    DIRECTION OUTPUT ;
    USE SIGNAL ;
    SHAPE ABUTMENT ;
    PORT
      LAYER M3 ;
      RECT 60.687 0.000 60.705 0.054 ;
    END
  END rw0_rd_out[40]
  PIN rw0_rd_out[41]
    DIRECTION OUTPUT ;
    USE SIGNAL ;
    SHAPE ABUTMENT ;
    PORT
      LAYER M3 ;
      RECT 61.263 0.000 61.281 0.054 ;
    END
  END rw0_rd_out[41]
  PIN rw0_rd_out[42]
    DIRECTION OUTPUT ;
    USE SIGNAL ;
    SHAPE ABUTMENT ;
    PORT
      LAYER M3 ;
      RECT 61.839 0.000 61.857 0.054 ;
    END
  END rw0_rd_out[42]
  PIN rw0_rd_out[43]
    DIRECTION OUTPUT ;
    USE SIGNAL ;
    SHAPE ABUTMENT ;
    PORT
      LAYER M3 ;
      RECT 62.415 0.000 62.433 0.054 ;
    END
  END rw0_rd_out[43]
  PIN rw0_rd_out[44]
    DIRECTION OUTPUT ;
    USE SIGNAL ;
    SHAPE ABUTMENT ;
    PORT
      LAYER M3 ;
      RECT 62.991 0.000 63.009 0.054 ;
    END
  END rw0_rd_out[44]
  PIN rw0_rd_out[45]
    DIRECTION OUTPUT ;
    USE SIGNAL ;
    SHAPE ABUTMENT ;
    PORT
      LAYER M3 ;
      RECT 63.567 0.000 63.585 0.054 ;
    END
  END rw0_rd_out[45]
  PIN rw0_rd_out[46]
    DIRECTION OUTPUT ;
    USE SIGNAL ;
    SHAPE ABUTMENT ;
    PORT
      LAYER M3 ;
      RECT 64.143 0.000 64.161 0.054 ;
    END
  END rw0_rd_out[46]
  PIN rw0_rd_out[47]
    DIRECTION OUTPUT ;
    USE SIGNAL ;
    SHAPE ABUTMENT ;
    PORT
      LAYER M3 ;
      RECT 64.719 0.000 64.737 0.054 ;
    END
  END rw0_rd_out[47]
  PIN rw0_rd_out[48]
    DIRECTION OUTPUT ;
    USE SIGNAL ;
    SHAPE ABUTMENT ;
    PORT
      LAYER M3 ;
      RECT 65.295 0.000 65.313 0.054 ;
    END
  END rw0_rd_out[48]
  PIN rw0_rd_out[49]
    DIRECTION OUTPUT ;
    USE SIGNAL ;
    SHAPE ABUTMENT ;
    PORT
      LAYER M3 ;
      RECT 65.871 0.000 65.889 0.054 ;
    END
  END rw0_rd_out[49]
  PIN rw0_rd_out[50]
    DIRECTION OUTPUT ;
    USE SIGNAL ;
    SHAPE ABUTMENT ;
    PORT
      LAYER M3 ;
      RECT 66.447 0.000 66.465 0.054 ;
    END
  END rw0_rd_out[50]
  PIN rw0_rd_out[51]
    DIRECTION OUTPUT ;
    USE SIGNAL ;
    SHAPE ABUTMENT ;
    PORT
      LAYER M3 ;
      RECT 67.023 0.000 67.041 0.054 ;
    END
  END rw0_rd_out[51]
  PIN rw0_rd_out[52]
    DIRECTION OUTPUT ;
    USE SIGNAL ;
    SHAPE ABUTMENT ;
    PORT
      LAYER M3 ;
      RECT 67.599 0.000 67.617 0.054 ;
    END
  END rw0_rd_out[52]
  PIN rw0_rd_out[53]
    DIRECTION OUTPUT ;
    USE SIGNAL ;
    SHAPE ABUTMENT ;
    PORT
      LAYER M3 ;
      RECT 68.175 0.000 68.193 0.054 ;
    END
  END rw0_rd_out[53]
  PIN rw0_rd_out[54]
    DIRECTION OUTPUT ;
    USE SIGNAL ;
    SHAPE ABUTMENT ;
    PORT
      LAYER M3 ;
      RECT 68.751 0.000 68.769 0.054 ;
    END
  END rw0_rd_out[54]
  PIN rw0_rd_out[55]
    DIRECTION OUTPUT ;
    USE SIGNAL ;
    SHAPE ABUTMENT ;
    PORT
      LAYER M3 ;
      RECT 69.327 0.000 69.345 0.054 ;
    END
  END rw0_rd_out[55]
  PIN rw0_rd_out[56]
    DIRECTION OUTPUT ;
    USE SIGNAL ;
    SHAPE ABUTMENT ;
    PORT
      LAYER M3 ;
      RECT 69.903 0.000 69.921 0.054 ;
    END
  END rw0_rd_out[56]
  PIN rw0_rd_out[57]
    DIRECTION OUTPUT ;
    USE SIGNAL ;
    SHAPE ABUTMENT ;
    PORT
      LAYER M3 ;
      RECT 70.479 0.000 70.497 0.054 ;
    END
  END rw0_rd_out[57]
  PIN rw0_rd_out[58]
    DIRECTION OUTPUT ;
    USE SIGNAL ;
    SHAPE ABUTMENT ;
    PORT
      LAYER M3 ;
      RECT 71.055 0.000 71.073 0.054 ;
    END
  END rw0_rd_out[58]
  PIN rw0_rd_out[59]
    DIRECTION OUTPUT ;
    USE SIGNAL ;
    SHAPE ABUTMENT ;
    PORT
      LAYER M3 ;
      RECT 71.631 0.000 71.649 0.054 ;
    END
  END rw0_rd_out[59]
  PIN rw0_rd_out[60]
    DIRECTION OUTPUT ;
    USE SIGNAL ;
    SHAPE ABUTMENT ;
    PORT
      LAYER M3 ;
      RECT 72.207 0.000 72.225 0.054 ;
    END
  END rw0_rd_out[60]
  PIN rw0_rd_out[61]
    DIRECTION OUTPUT ;
    USE SIGNAL ;
    SHAPE ABUTMENT ;
    PORT
      LAYER M3 ;
      RECT 72.783 0.000 72.801 0.054 ;
    END
  END rw0_rd_out[61]
  PIN rw0_rd_out[62]
    DIRECTION OUTPUT ;
    USE SIGNAL ;
    SHAPE ABUTMENT ;
    PORT
      LAYER M3 ;
      RECT 73.359 0.000 73.377 0.054 ;
    END
  END rw0_rd_out[62]
  PIN rw0_rd_out[63]
    DIRECTION OUTPUT ;
    USE SIGNAL ;
    SHAPE ABUTMENT ;
    PORT
      LAYER M3 ;
      RECT 73.935 0.000 73.953 0.054 ;
    END
  END rw0_rd_out[63]
  PIN rw0_rd_out[64]
    DIRECTION OUTPUT ;
    USE SIGNAL ;
    SHAPE ABUTMENT ;
    PORT
      LAYER M3 ;
      RECT 74.511 0.000 74.529 0.054 ;
    END
  END rw0_rd_out[64]
  PIN rw0_rd_out[65]
    DIRECTION OUTPUT ;
    USE SIGNAL ;
    SHAPE ABUTMENT ;
    PORT
      LAYER M3 ;
      RECT 0.207 73.387 0.225 73.441 ;
    END
  END rw0_rd_out[65]
  PIN rw0_rd_out[66]
    DIRECTION OUTPUT ;
    USE SIGNAL ;
    SHAPE ABUTMENT ;
    PORT
      LAYER M3 ;
      RECT 1.071 73.387 1.089 73.441 ;
    END
  END rw0_rd_out[66]
  PIN rw0_rd_out[67]
    DIRECTION OUTPUT ;
    USE SIGNAL ;
    SHAPE ABUTMENT ;
    PORT
      LAYER M3 ;
      RECT 1.935 73.387 1.953 73.441 ;
    END
  END rw0_rd_out[67]
  PIN rw0_rd_out[68]
    DIRECTION OUTPUT ;
    USE SIGNAL ;
    SHAPE ABUTMENT ;
    PORT
      LAYER M3 ;
      RECT 2.799 73.387 2.817 73.441 ;
    END
  END rw0_rd_out[68]
  PIN rw0_rd_out[69]
    DIRECTION OUTPUT ;
    USE SIGNAL ;
    SHAPE ABUTMENT ;
    PORT
      LAYER M3 ;
      RECT 3.663 73.387 3.681 73.441 ;
    END
  END rw0_rd_out[69]
  PIN rw0_rd_out[70]
    DIRECTION OUTPUT ;
    USE SIGNAL ;
    SHAPE ABUTMENT ;
    PORT
      LAYER M3 ;
      RECT 4.527 73.387 4.545 73.441 ;
    END
  END rw0_rd_out[70]
  PIN rw0_rd_out[71]
    DIRECTION OUTPUT ;
    USE SIGNAL ;
    SHAPE ABUTMENT ;
    PORT
      LAYER M3 ;
      RECT 5.391 73.387 5.409 73.441 ;
    END
  END rw0_rd_out[71]
  PIN rw0_rd_out[72]
    DIRECTION OUTPUT ;
    USE SIGNAL ;
    SHAPE ABUTMENT ;
    PORT
      LAYER M3 ;
      RECT 6.255 73.387 6.273 73.441 ;
    END
  END rw0_rd_out[72]
  PIN rw0_rd_out[73]
    DIRECTION OUTPUT ;
    USE SIGNAL ;
    SHAPE ABUTMENT ;
    PORT
      LAYER M3 ;
      RECT 7.119 73.387 7.137 73.441 ;
    END
  END rw0_rd_out[73]
  PIN rw0_rd_out[74]
    DIRECTION OUTPUT ;
    USE SIGNAL ;
    SHAPE ABUTMENT ;
    PORT
      LAYER M3 ;
      RECT 7.983 73.387 8.001 73.441 ;
    END
  END rw0_rd_out[74]
  PIN rw0_rd_out[75]
    DIRECTION OUTPUT ;
    USE SIGNAL ;
    SHAPE ABUTMENT ;
    PORT
      LAYER M3 ;
      RECT 8.847 73.387 8.865 73.441 ;
    END
  END rw0_rd_out[75]
  PIN rw0_rd_out[76]
    DIRECTION OUTPUT ;
    USE SIGNAL ;
    SHAPE ABUTMENT ;
    PORT
      LAYER M3 ;
      RECT 9.711 73.387 9.729 73.441 ;
    END
  END rw0_rd_out[76]
  PIN rw0_rd_out[77]
    DIRECTION OUTPUT ;
    USE SIGNAL ;
    SHAPE ABUTMENT ;
    PORT
      LAYER M3 ;
      RECT 10.575 73.387 10.593 73.441 ;
    END
  END rw0_rd_out[77]
  PIN rw0_rd_out[78]
    DIRECTION OUTPUT ;
    USE SIGNAL ;
    SHAPE ABUTMENT ;
    PORT
      LAYER M3 ;
      RECT 11.439 73.387 11.457 73.441 ;
    END
  END rw0_rd_out[78]
  PIN rw0_rd_out[79]
    DIRECTION OUTPUT ;
    USE SIGNAL ;
    SHAPE ABUTMENT ;
    PORT
      LAYER M3 ;
      RECT 12.303 73.387 12.321 73.441 ;
    END
  END rw0_rd_out[79]
  PIN rw0_rd_out[80]
    DIRECTION OUTPUT ;
    USE SIGNAL ;
    SHAPE ABUTMENT ;
    PORT
      LAYER M3 ;
      RECT 13.167 73.387 13.185 73.441 ;
    END
  END rw0_rd_out[80]
  PIN rw0_rd_out[81]
    DIRECTION OUTPUT ;
    USE SIGNAL ;
    SHAPE ABUTMENT ;
    PORT
      LAYER M3 ;
      RECT 14.031 73.387 14.049 73.441 ;
    END
  END rw0_rd_out[81]
  PIN rw0_rd_out[82]
    DIRECTION OUTPUT ;
    USE SIGNAL ;
    SHAPE ABUTMENT ;
    PORT
      LAYER M3 ;
      RECT 14.895 73.387 14.913 73.441 ;
    END
  END rw0_rd_out[82]
  PIN rw0_rd_out[83]
    DIRECTION OUTPUT ;
    USE SIGNAL ;
    SHAPE ABUTMENT ;
    PORT
      LAYER M3 ;
      RECT 15.759 73.387 15.777 73.441 ;
    END
  END rw0_rd_out[83]
  PIN rw0_rd_out[84]
    DIRECTION OUTPUT ;
    USE SIGNAL ;
    SHAPE ABUTMENT ;
    PORT
      LAYER M3 ;
      RECT 16.623 73.387 16.641 73.441 ;
    END
  END rw0_rd_out[84]
  PIN rw0_rd_out[85]
    DIRECTION OUTPUT ;
    USE SIGNAL ;
    SHAPE ABUTMENT ;
    PORT
      LAYER M3 ;
      RECT 17.487 73.387 17.505 73.441 ;
    END
  END rw0_rd_out[85]
  PIN rw0_rd_out[86]
    DIRECTION OUTPUT ;
    USE SIGNAL ;
    SHAPE ABUTMENT ;
    PORT
      LAYER M3 ;
      RECT 18.351 73.387 18.369 73.441 ;
    END
  END rw0_rd_out[86]
  PIN rw0_rd_out[87]
    DIRECTION OUTPUT ;
    USE SIGNAL ;
    SHAPE ABUTMENT ;
    PORT
      LAYER M3 ;
      RECT 19.215 73.387 19.233 73.441 ;
    END
  END rw0_rd_out[87]
  PIN rw0_rd_out[88]
    DIRECTION OUTPUT ;
    USE SIGNAL ;
    SHAPE ABUTMENT ;
    PORT
      LAYER M3 ;
      RECT 20.079 73.387 20.097 73.441 ;
    END
  END rw0_rd_out[88]
  PIN rw0_rd_out[89]
    DIRECTION OUTPUT ;
    USE SIGNAL ;
    SHAPE ABUTMENT ;
    PORT
      LAYER M3 ;
      RECT 20.943 73.387 20.961 73.441 ;
    END
  END rw0_rd_out[89]
  PIN rw0_rd_out[90]
    DIRECTION OUTPUT ;
    USE SIGNAL ;
    SHAPE ABUTMENT ;
    PORT
      LAYER M3 ;
      RECT 21.807 73.387 21.825 73.441 ;
    END
  END rw0_rd_out[90]
  PIN rw0_rd_out[91]
    DIRECTION OUTPUT ;
    USE SIGNAL ;
    SHAPE ABUTMENT ;
    PORT
      LAYER M3 ;
      RECT 22.671 73.387 22.689 73.441 ;
    END
  END rw0_rd_out[91]
  PIN rw0_rd_out[92]
    DIRECTION OUTPUT ;
    USE SIGNAL ;
    SHAPE ABUTMENT ;
    PORT
      LAYER M3 ;
      RECT 23.535 73.387 23.553 73.441 ;
    END
  END rw0_rd_out[92]
  PIN rw0_rd_out[93]
    DIRECTION OUTPUT ;
    USE SIGNAL ;
    SHAPE ABUTMENT ;
    PORT
      LAYER M3 ;
      RECT 24.399 73.387 24.417 73.441 ;
    END
  END rw0_rd_out[93]
  PIN rw0_rd_out[94]
    DIRECTION OUTPUT ;
    USE SIGNAL ;
    SHAPE ABUTMENT ;
    PORT
      LAYER M3 ;
      RECT 25.263 73.387 25.281 73.441 ;
    END
  END rw0_rd_out[94]
  PIN rw0_rd_out[95]
    DIRECTION OUTPUT ;
    USE SIGNAL ;
    SHAPE ABUTMENT ;
    PORT
      LAYER M3 ;
      RECT 26.127 73.387 26.145 73.441 ;
    END
  END rw0_rd_out[95]
  PIN rw0_rd_out[96]
    DIRECTION OUTPUT ;
    USE SIGNAL ;
    SHAPE ABUTMENT ;
    PORT
      LAYER M3 ;
      RECT 26.991 73.387 27.009 73.441 ;
    END
  END rw0_rd_out[96]
  PIN rw0_rd_out[97]
    DIRECTION OUTPUT ;
    USE SIGNAL ;
    SHAPE ABUTMENT ;
    PORT
      LAYER M3 ;
      RECT 27.855 73.387 27.873 73.441 ;
    END
  END rw0_rd_out[97]
  PIN rw0_rd_out[98]
    DIRECTION OUTPUT ;
    USE SIGNAL ;
    SHAPE ABUTMENT ;
    PORT
      LAYER M3 ;
      RECT 28.719 73.387 28.737 73.441 ;
    END
  END rw0_rd_out[98]
  PIN rw0_rd_out[99]
    DIRECTION OUTPUT ;
    USE SIGNAL ;
    SHAPE ABUTMENT ;
    PORT
      LAYER M3 ;
      RECT 29.583 73.387 29.601 73.441 ;
    END
  END rw0_rd_out[99]
  PIN rw0_rd_out[100]
    DIRECTION OUTPUT ;
    USE SIGNAL ;
    SHAPE ABUTMENT ;
    PORT
      LAYER M3 ;
      RECT 30.447 73.387 30.465 73.441 ;
    END
  END rw0_rd_out[100]
  PIN rw0_rd_out[101]
    DIRECTION OUTPUT ;
    USE SIGNAL ;
    SHAPE ABUTMENT ;
    PORT
      LAYER M3 ;
      RECT 31.311 73.387 31.329 73.441 ;
    END
  END rw0_rd_out[101]
  PIN rw0_rd_out[102]
    DIRECTION OUTPUT ;
    USE SIGNAL ;
    SHAPE ABUTMENT ;
    PORT
      LAYER M3 ;
      RECT 32.175 73.387 32.193 73.441 ;
    END
  END rw0_rd_out[102]
  PIN rw0_rd_out[103]
    DIRECTION OUTPUT ;
    USE SIGNAL ;
    SHAPE ABUTMENT ;
    PORT
      LAYER M3 ;
      RECT 33.039 73.387 33.057 73.441 ;
    END
  END rw0_rd_out[103]
  PIN rw0_rd_out[104]
    DIRECTION OUTPUT ;
    USE SIGNAL ;
    SHAPE ABUTMENT ;
    PORT
      LAYER M3 ;
      RECT 33.903 73.387 33.921 73.441 ;
    END
  END rw0_rd_out[104]
  PIN rw0_rd_out[105]
    DIRECTION OUTPUT ;
    USE SIGNAL ;
    SHAPE ABUTMENT ;
    PORT
      LAYER M3 ;
      RECT 34.767 73.387 34.785 73.441 ;
    END
  END rw0_rd_out[105]
  PIN rw0_rd_out[106]
    DIRECTION OUTPUT ;
    USE SIGNAL ;
    SHAPE ABUTMENT ;
    PORT
      LAYER M3 ;
      RECT 35.631 73.387 35.649 73.441 ;
    END
  END rw0_rd_out[106]
  PIN rw0_rd_out[107]
    DIRECTION OUTPUT ;
    USE SIGNAL ;
    SHAPE ABUTMENT ;
    PORT
      LAYER M3 ;
      RECT 36.495 73.387 36.513 73.441 ;
    END
  END rw0_rd_out[107]
  PIN rw0_rd_out[108]
    DIRECTION OUTPUT ;
    USE SIGNAL ;
    SHAPE ABUTMENT ;
    PORT
      LAYER M3 ;
      RECT 37.359 73.387 37.377 73.441 ;
    END
  END rw0_rd_out[108]
  PIN rw0_rd_out[109]
    DIRECTION OUTPUT ;
    USE SIGNAL ;
    SHAPE ABUTMENT ;
    PORT
      LAYER M3 ;
      RECT 38.223 73.387 38.241 73.441 ;
    END
  END rw0_rd_out[109]
  PIN rw0_rd_out[110]
    DIRECTION OUTPUT ;
    USE SIGNAL ;
    SHAPE ABUTMENT ;
    PORT
      LAYER M3 ;
      RECT 39.087 73.387 39.105 73.441 ;
    END
  END rw0_rd_out[110]
  PIN rw0_rd_out[111]
    DIRECTION OUTPUT ;
    USE SIGNAL ;
    SHAPE ABUTMENT ;
    PORT
      LAYER M3 ;
      RECT 39.951 73.387 39.969 73.441 ;
    END
  END rw0_rd_out[111]
  PIN rw0_rd_out[112]
    DIRECTION OUTPUT ;
    USE SIGNAL ;
    SHAPE ABUTMENT ;
    PORT
      LAYER M3 ;
      RECT 40.815 73.387 40.833 73.441 ;
    END
  END rw0_rd_out[112]
  PIN rw0_rd_out[113]
    DIRECTION OUTPUT ;
    USE SIGNAL ;
    SHAPE ABUTMENT ;
    PORT
      LAYER M3 ;
      RECT 41.679 73.387 41.697 73.441 ;
    END
  END rw0_rd_out[113]
  PIN rw0_rd_out[114]
    DIRECTION OUTPUT ;
    USE SIGNAL ;
    SHAPE ABUTMENT ;
    PORT
      LAYER M3 ;
      RECT 42.543 73.387 42.561 73.441 ;
    END
  END rw0_rd_out[114]
  PIN rw0_rd_out[115]
    DIRECTION OUTPUT ;
    USE SIGNAL ;
    SHAPE ABUTMENT ;
    PORT
      LAYER M3 ;
      RECT 43.407 73.387 43.425 73.441 ;
    END
  END rw0_rd_out[115]
  PIN rw0_rd_out[116]
    DIRECTION OUTPUT ;
    USE SIGNAL ;
    SHAPE ABUTMENT ;
    PORT
      LAYER M3 ;
      RECT 44.271 73.387 44.289 73.441 ;
    END
  END rw0_rd_out[116]
  PIN rw0_rd_out[117]
    DIRECTION OUTPUT ;
    USE SIGNAL ;
    SHAPE ABUTMENT ;
    PORT
      LAYER M3 ;
      RECT 45.135 73.387 45.153 73.441 ;
    END
  END rw0_rd_out[117]
  PIN rw0_rd_out[118]
    DIRECTION OUTPUT ;
    USE SIGNAL ;
    SHAPE ABUTMENT ;
    PORT
      LAYER M3 ;
      RECT 45.999 73.387 46.017 73.441 ;
    END
  END rw0_rd_out[118]
  PIN rw0_rd_out[119]
    DIRECTION OUTPUT ;
    USE SIGNAL ;
    SHAPE ABUTMENT ;
    PORT
      LAYER M3 ;
      RECT 46.863 73.387 46.881 73.441 ;
    END
  END rw0_rd_out[119]
  PIN rw0_rd_out[120]
    DIRECTION OUTPUT ;
    USE SIGNAL ;
    SHAPE ABUTMENT ;
    PORT
      LAYER M3 ;
      RECT 47.727 73.387 47.745 73.441 ;
    END
  END rw0_rd_out[120]
  PIN rw0_rd_out[121]
    DIRECTION OUTPUT ;
    USE SIGNAL ;
    SHAPE ABUTMENT ;
    PORT
      LAYER M3 ;
      RECT 48.591 73.387 48.609 73.441 ;
    END
  END rw0_rd_out[121]
  PIN rw0_rd_out[122]
    DIRECTION OUTPUT ;
    USE SIGNAL ;
    SHAPE ABUTMENT ;
    PORT
      LAYER M3 ;
      RECT 49.455 73.387 49.473 73.441 ;
    END
  END rw0_rd_out[122]
  PIN rw0_rd_out[123]
    DIRECTION OUTPUT ;
    USE SIGNAL ;
    SHAPE ABUTMENT ;
    PORT
      LAYER M3 ;
      RECT 50.319 73.387 50.337 73.441 ;
    END
  END rw0_rd_out[123]
  PIN rw0_rd_out[124]
    DIRECTION OUTPUT ;
    USE SIGNAL ;
    SHAPE ABUTMENT ;
    PORT
      LAYER M3 ;
      RECT 51.183 73.387 51.201 73.441 ;
    END
  END rw0_rd_out[124]
  PIN rw0_rd_out[125]
    DIRECTION OUTPUT ;
    USE SIGNAL ;
    SHAPE ABUTMENT ;
    PORT
      LAYER M3 ;
      RECT 52.047 73.387 52.065 73.441 ;
    END
  END rw0_rd_out[125]
  PIN rw0_rd_out[126]
    DIRECTION OUTPUT ;
    USE SIGNAL ;
    SHAPE ABUTMENT ;
    PORT
      LAYER M3 ;
      RECT 52.911 73.387 52.929 73.441 ;
    END
  END rw0_rd_out[126]
  PIN rw0_rd_out[127]
    DIRECTION OUTPUT ;
    USE SIGNAL ;
    SHAPE ABUTMENT ;
    PORT
      LAYER M3 ;
      RECT 53.775 73.387 53.793 73.441 ;
    END
  END rw0_rd_out[127]
  PIN rw0_rd_out[128]
    DIRECTION OUTPUT ;
    USE SIGNAL ;
    SHAPE ABUTMENT ;
    PORT
      LAYER M3 ;
      RECT 54.639 73.387 54.657 73.441 ;
    END
  END rw0_rd_out[128]
  PIN rw0_rd_out[129]
    DIRECTION OUTPUT ;
    USE SIGNAL ;
    SHAPE ABUTMENT ;
    PORT
      LAYER M3 ;
      RECT 55.503 73.387 55.521 73.441 ;
    END
  END rw0_rd_out[129]
  PIN r0_rd_out[0]
    DIRECTION OUTPUT ;
    USE SIGNAL ;
    SHAPE ABUTMENT ;
    PORT
      LAYER M3 ;
      RECT 75.087 0.000 75.105 0.054 ;
    END
  END r0_rd_out[0]
  PIN r0_rd_out[1]
    DIRECTION OUTPUT ;
    USE SIGNAL ;
    SHAPE ABUTMENT ;
    PORT
      LAYER M3 ;
      RECT 75.663 0.000 75.681 0.054 ;
    END
  END r0_rd_out[1]
  PIN r0_rd_out[2]
    DIRECTION OUTPUT ;
    USE SIGNAL ;
    SHAPE ABUTMENT ;
    PORT
      LAYER M3 ;
      RECT 76.239 0.000 76.257 0.054 ;
    END
  END r0_rd_out[2]
  PIN r0_rd_out[3]
    DIRECTION OUTPUT ;
    USE SIGNAL ;
    SHAPE ABUTMENT ;
    PORT
      LAYER M3 ;
      RECT 76.815 0.000 76.833 0.054 ;
    END
  END r0_rd_out[3]
  PIN r0_rd_out[4]
    DIRECTION OUTPUT ;
    USE SIGNAL ;
    SHAPE ABUTMENT ;
    PORT
      LAYER M3 ;
      RECT 77.391 0.000 77.409 0.054 ;
    END
  END r0_rd_out[4]
  PIN r0_rd_out[5]
    DIRECTION OUTPUT ;
    USE SIGNAL ;
    SHAPE ABUTMENT ;
    PORT
      LAYER M3 ;
      RECT 77.967 0.000 77.985 0.054 ;
    END
  END r0_rd_out[5]
  PIN r0_rd_out[6]
    DIRECTION OUTPUT ;
    USE SIGNAL ;
    SHAPE ABUTMENT ;
    PORT
      LAYER M3 ;
      RECT 78.543 0.000 78.561 0.054 ;
    END
  END r0_rd_out[6]
  PIN r0_rd_out[7]
    DIRECTION OUTPUT ;
    USE SIGNAL ;
    SHAPE ABUTMENT ;
    PORT
      LAYER M3 ;
      RECT 79.119 0.000 79.137 0.054 ;
    END
  END r0_rd_out[7]
  PIN r0_rd_out[8]
    DIRECTION OUTPUT ;
    USE SIGNAL ;
    SHAPE ABUTMENT ;
    PORT
      LAYER M3 ;
      RECT 79.695 0.000 79.713 0.054 ;
    END
  END r0_rd_out[8]
  PIN r0_rd_out[9]
    DIRECTION OUTPUT ;
    USE SIGNAL ;
    SHAPE ABUTMENT ;
    PORT
      LAYER M3 ;
      RECT 80.271 0.000 80.289 0.054 ;
    END
  END r0_rd_out[9]
  PIN r0_rd_out[10]
    DIRECTION OUTPUT ;
    USE SIGNAL ;
    SHAPE ABUTMENT ;
    PORT
      LAYER M3 ;
      RECT 80.847 0.000 80.865 0.054 ;
    END
  END r0_rd_out[10]
  PIN r0_rd_out[11]
    DIRECTION OUTPUT ;
    USE SIGNAL ;
    SHAPE ABUTMENT ;
    PORT
      LAYER M3 ;
      RECT 81.423 0.000 81.441 0.054 ;
    END
  END r0_rd_out[11]
  PIN r0_rd_out[12]
    DIRECTION OUTPUT ;
    USE SIGNAL ;
    SHAPE ABUTMENT ;
    PORT
      LAYER M3 ;
      RECT 81.999 0.000 82.017 0.054 ;
    END
  END r0_rd_out[12]
  PIN r0_rd_out[13]
    DIRECTION OUTPUT ;
    USE SIGNAL ;
    SHAPE ABUTMENT ;
    PORT
      LAYER M3 ;
      RECT 82.575 0.000 82.593 0.054 ;
    END
  END r0_rd_out[13]
  PIN r0_rd_out[14]
    DIRECTION OUTPUT ;
    USE SIGNAL ;
    SHAPE ABUTMENT ;
    PORT
      LAYER M3 ;
      RECT 83.151 0.000 83.169 0.054 ;
    END
  END r0_rd_out[14]
  PIN r0_rd_out[15]
    DIRECTION OUTPUT ;
    USE SIGNAL ;
    SHAPE ABUTMENT ;
    PORT
      LAYER M3 ;
      RECT 83.727 0.000 83.745 0.054 ;
    END
  END r0_rd_out[15]
  PIN r0_rd_out[16]
    DIRECTION OUTPUT ;
    USE SIGNAL ;
    SHAPE ABUTMENT ;
    PORT
      LAYER M3 ;
      RECT 84.303 0.000 84.321 0.054 ;
    END
  END r0_rd_out[16]
  PIN r0_rd_out[17]
    DIRECTION OUTPUT ;
    USE SIGNAL ;
    SHAPE ABUTMENT ;
    PORT
      LAYER M3 ;
      RECT 84.879 0.000 84.897 0.054 ;
    END
  END r0_rd_out[17]
  PIN r0_rd_out[18]
    DIRECTION OUTPUT ;
    USE SIGNAL ;
    SHAPE ABUTMENT ;
    PORT
      LAYER M3 ;
      RECT 85.455 0.000 85.473 0.054 ;
    END
  END r0_rd_out[18]
  PIN r0_rd_out[19]
    DIRECTION OUTPUT ;
    USE SIGNAL ;
    SHAPE ABUTMENT ;
    PORT
      LAYER M3 ;
      RECT 86.031 0.000 86.049 0.054 ;
    END
  END r0_rd_out[19]
  PIN r0_rd_out[20]
    DIRECTION OUTPUT ;
    USE SIGNAL ;
    SHAPE ABUTMENT ;
    PORT
      LAYER M3 ;
      RECT 86.607 0.000 86.625 0.054 ;
    END
  END r0_rd_out[20]
  PIN r0_rd_out[21]
    DIRECTION OUTPUT ;
    USE SIGNAL ;
    SHAPE ABUTMENT ;
    PORT
      LAYER M3 ;
      RECT 87.183 0.000 87.201 0.054 ;
    END
  END r0_rd_out[21]
  PIN r0_rd_out[22]
    DIRECTION OUTPUT ;
    USE SIGNAL ;
    SHAPE ABUTMENT ;
    PORT
      LAYER M3 ;
      RECT 87.759 0.000 87.777 0.054 ;
    END
  END r0_rd_out[22]
  PIN r0_rd_out[23]
    DIRECTION OUTPUT ;
    USE SIGNAL ;
    SHAPE ABUTMENT ;
    PORT
      LAYER M3 ;
      RECT 88.335 0.000 88.353 0.054 ;
    END
  END r0_rd_out[23]
  PIN r0_rd_out[24]
    DIRECTION OUTPUT ;
    USE SIGNAL ;
    SHAPE ABUTMENT ;
    PORT
      LAYER M3 ;
      RECT 88.911 0.000 88.929 0.054 ;
    END
  END r0_rd_out[24]
  PIN r0_rd_out[25]
    DIRECTION OUTPUT ;
    USE SIGNAL ;
    SHAPE ABUTMENT ;
    PORT
      LAYER M3 ;
      RECT 89.487 0.000 89.505 0.054 ;
    END
  END r0_rd_out[25]
  PIN r0_rd_out[26]
    DIRECTION OUTPUT ;
    USE SIGNAL ;
    SHAPE ABUTMENT ;
    PORT
      LAYER M3 ;
      RECT 90.063 0.000 90.081 0.054 ;
    END
  END r0_rd_out[26]
  PIN r0_rd_out[27]
    DIRECTION OUTPUT ;
    USE SIGNAL ;
    SHAPE ABUTMENT ;
    PORT
      LAYER M3 ;
      RECT 90.639 0.000 90.657 0.054 ;
    END
  END r0_rd_out[27]
  PIN r0_rd_out[28]
    DIRECTION OUTPUT ;
    USE SIGNAL ;
    SHAPE ABUTMENT ;
    PORT
      LAYER M3 ;
      RECT 91.215 0.000 91.233 0.054 ;
    END
  END r0_rd_out[28]
  PIN r0_rd_out[29]
    DIRECTION OUTPUT ;
    USE SIGNAL ;
    SHAPE ABUTMENT ;
    PORT
      LAYER M3 ;
      RECT 91.791 0.000 91.809 0.054 ;
    END
  END r0_rd_out[29]
  PIN r0_rd_out[30]
    DIRECTION OUTPUT ;
    USE SIGNAL ;
    SHAPE ABUTMENT ;
    PORT
      LAYER M3 ;
      RECT 92.367 0.000 92.385 0.054 ;
    END
  END r0_rd_out[30]
  PIN r0_rd_out[31]
    DIRECTION OUTPUT ;
    USE SIGNAL ;
    SHAPE ABUTMENT ;
    PORT
      LAYER M3 ;
      RECT 92.943 0.000 92.961 0.054 ;
    END
  END r0_rd_out[31]
  PIN r0_rd_out[32]
    DIRECTION OUTPUT ;
    USE SIGNAL ;
    SHAPE ABUTMENT ;
    PORT
      LAYER M3 ;
      RECT 93.519 0.000 93.537 0.054 ;
    END
  END r0_rd_out[32]
  PIN r0_rd_out[33]
    DIRECTION OUTPUT ;
    USE SIGNAL ;
    SHAPE ABUTMENT ;
    PORT
      LAYER M3 ;
      RECT 94.095 0.000 94.113 0.054 ;
    END
  END r0_rd_out[33]
  PIN r0_rd_out[34]
    DIRECTION OUTPUT ;
    USE SIGNAL ;
    SHAPE ABUTMENT ;
    PORT
      LAYER M3 ;
      RECT 94.671 0.000 94.689 0.054 ;
    END
  END r0_rd_out[34]
  PIN r0_rd_out[35]
    DIRECTION OUTPUT ;
    USE SIGNAL ;
    SHAPE ABUTMENT ;
    PORT
      LAYER M3 ;
      RECT 95.247 0.000 95.265 0.054 ;
    END
  END r0_rd_out[35]
  PIN r0_rd_out[36]
    DIRECTION OUTPUT ;
    USE SIGNAL ;
    SHAPE ABUTMENT ;
    PORT
      LAYER M3 ;
      RECT 95.823 0.000 95.841 0.054 ;
    END
  END r0_rd_out[36]
  PIN r0_rd_out[37]
    DIRECTION OUTPUT ;
    USE SIGNAL ;
    SHAPE ABUTMENT ;
    PORT
      LAYER M3 ;
      RECT 96.399 0.000 96.417 0.054 ;
    END
  END r0_rd_out[37]
  PIN r0_rd_out[38]
    DIRECTION OUTPUT ;
    USE SIGNAL ;
    SHAPE ABUTMENT ;
    PORT
      LAYER M3 ;
      RECT 96.975 0.000 96.993 0.054 ;
    END
  END r0_rd_out[38]
  PIN r0_rd_out[39]
    DIRECTION OUTPUT ;
    USE SIGNAL ;
    SHAPE ABUTMENT ;
    PORT
      LAYER M3 ;
      RECT 97.551 0.000 97.569 0.054 ;
    END
  END r0_rd_out[39]
  PIN r0_rd_out[40]
    DIRECTION OUTPUT ;
    USE SIGNAL ;
    SHAPE ABUTMENT ;
    PORT
      LAYER M3 ;
      RECT 98.127 0.000 98.145 0.054 ;
    END
  END r0_rd_out[40]
  PIN r0_rd_out[41]
    DIRECTION OUTPUT ;
    USE SIGNAL ;
    SHAPE ABUTMENT ;
    PORT
      LAYER M3 ;
      RECT 98.703 0.000 98.721 0.054 ;
    END
  END r0_rd_out[41]
  PIN r0_rd_out[42]
    DIRECTION OUTPUT ;
    USE SIGNAL ;
    SHAPE ABUTMENT ;
    PORT
      LAYER M3 ;
      RECT 99.279 0.000 99.297 0.054 ;
    END
  END r0_rd_out[42]
  PIN r0_rd_out[43]
    DIRECTION OUTPUT ;
    USE SIGNAL ;
    SHAPE ABUTMENT ;
    PORT
      LAYER M3 ;
      RECT 99.855 0.000 99.873 0.054 ;
    END
  END r0_rd_out[43]
  PIN r0_rd_out[44]
    DIRECTION OUTPUT ;
    USE SIGNAL ;
    SHAPE ABUTMENT ;
    PORT
      LAYER M3 ;
      RECT 100.431 0.000 100.449 0.054 ;
    END
  END r0_rd_out[44]
  PIN r0_rd_out[45]
    DIRECTION OUTPUT ;
    USE SIGNAL ;
    SHAPE ABUTMENT ;
    PORT
      LAYER M3 ;
      RECT 101.007 0.000 101.025 0.054 ;
    END
  END r0_rd_out[45]
  PIN r0_rd_out[46]
    DIRECTION OUTPUT ;
    USE SIGNAL ;
    SHAPE ABUTMENT ;
    PORT
      LAYER M3 ;
      RECT 101.583 0.000 101.601 0.054 ;
    END
  END r0_rd_out[46]
  PIN r0_rd_out[47]
    DIRECTION OUTPUT ;
    USE SIGNAL ;
    SHAPE ABUTMENT ;
    PORT
      LAYER M3 ;
      RECT 102.159 0.000 102.177 0.054 ;
    END
  END r0_rd_out[47]
  PIN r0_rd_out[48]
    DIRECTION OUTPUT ;
    USE SIGNAL ;
    SHAPE ABUTMENT ;
    PORT
      LAYER M3 ;
      RECT 102.735 0.000 102.753 0.054 ;
    END
  END r0_rd_out[48]
  PIN r0_rd_out[49]
    DIRECTION OUTPUT ;
    USE SIGNAL ;
    SHAPE ABUTMENT ;
    PORT
      LAYER M3 ;
      RECT 103.311 0.000 103.329 0.054 ;
    END
  END r0_rd_out[49]
  PIN r0_rd_out[50]
    DIRECTION OUTPUT ;
    USE SIGNAL ;
    SHAPE ABUTMENT ;
    PORT
      LAYER M3 ;
      RECT 103.887 0.000 103.905 0.054 ;
    END
  END r0_rd_out[50]
  PIN r0_rd_out[51]
    DIRECTION OUTPUT ;
    USE SIGNAL ;
    SHAPE ABUTMENT ;
    PORT
      LAYER M3 ;
      RECT 104.463 0.000 104.481 0.054 ;
    END
  END r0_rd_out[51]
  PIN r0_rd_out[52]
    DIRECTION OUTPUT ;
    USE SIGNAL ;
    SHAPE ABUTMENT ;
    PORT
      LAYER M3 ;
      RECT 105.039 0.000 105.057 0.054 ;
    END
  END r0_rd_out[52]
  PIN r0_rd_out[53]
    DIRECTION OUTPUT ;
    USE SIGNAL ;
    SHAPE ABUTMENT ;
    PORT
      LAYER M3 ;
      RECT 105.615 0.000 105.633 0.054 ;
    END
  END r0_rd_out[53]
  PIN r0_rd_out[54]
    DIRECTION OUTPUT ;
    USE SIGNAL ;
    SHAPE ABUTMENT ;
    PORT
      LAYER M3 ;
      RECT 106.191 0.000 106.209 0.054 ;
    END
  END r0_rd_out[54]
  PIN r0_rd_out[55]
    DIRECTION OUTPUT ;
    USE SIGNAL ;
    SHAPE ABUTMENT ;
    PORT
      LAYER M3 ;
      RECT 106.767 0.000 106.785 0.054 ;
    END
  END r0_rd_out[55]
  PIN r0_rd_out[56]
    DIRECTION OUTPUT ;
    USE SIGNAL ;
    SHAPE ABUTMENT ;
    PORT
      LAYER M3 ;
      RECT 107.343 0.000 107.361 0.054 ;
    END
  END r0_rd_out[56]
  PIN r0_rd_out[57]
    DIRECTION OUTPUT ;
    USE SIGNAL ;
    SHAPE ABUTMENT ;
    PORT
      LAYER M3 ;
      RECT 107.919 0.000 107.937 0.054 ;
    END
  END r0_rd_out[57]
  PIN r0_rd_out[58]
    DIRECTION OUTPUT ;
    USE SIGNAL ;
    SHAPE ABUTMENT ;
    PORT
      LAYER M3 ;
      RECT 108.495 0.000 108.513 0.054 ;
    END
  END r0_rd_out[58]
  PIN r0_rd_out[59]
    DIRECTION OUTPUT ;
    USE SIGNAL ;
    SHAPE ABUTMENT ;
    PORT
      LAYER M3 ;
      RECT 109.071 0.000 109.089 0.054 ;
    END
  END r0_rd_out[59]
  PIN r0_rd_out[60]
    DIRECTION OUTPUT ;
    USE SIGNAL ;
    SHAPE ABUTMENT ;
    PORT
      LAYER M3 ;
      RECT 109.647 0.000 109.665 0.054 ;
    END
  END r0_rd_out[60]
  PIN r0_rd_out[61]
    DIRECTION OUTPUT ;
    USE SIGNAL ;
    SHAPE ABUTMENT ;
    PORT
      LAYER M3 ;
      RECT 110.223 0.000 110.241 0.054 ;
    END
  END r0_rd_out[61]
  PIN r0_rd_out[62]
    DIRECTION OUTPUT ;
    USE SIGNAL ;
    SHAPE ABUTMENT ;
    PORT
      LAYER M3 ;
      RECT 110.799 0.000 110.817 0.054 ;
    END
  END r0_rd_out[62]
  PIN r0_rd_out[63]
    DIRECTION OUTPUT ;
    USE SIGNAL ;
    SHAPE ABUTMENT ;
    PORT
      LAYER M3 ;
      RECT 111.375 0.000 111.393 0.054 ;
    END
  END r0_rd_out[63]
  PIN r0_rd_out[64]
    DIRECTION OUTPUT ;
    USE SIGNAL ;
    SHAPE ABUTMENT ;
    PORT
      LAYER M3 ;
      RECT 111.951 0.000 111.969 0.054 ;
    END
  END r0_rd_out[64]
  PIN r0_rd_out[65]
    DIRECTION OUTPUT ;
    USE SIGNAL ;
    SHAPE ABUTMENT ;
    PORT
      LAYER M3 ;
      RECT 56.367 73.387 56.385 73.441 ;
    END
  END r0_rd_out[65]
  PIN r0_rd_out[66]
    DIRECTION OUTPUT ;
    USE SIGNAL ;
    SHAPE ABUTMENT ;
    PORT
      LAYER M3 ;
      RECT 57.231 73.387 57.249 73.441 ;
    END
  END r0_rd_out[66]
  PIN r0_rd_out[67]
    DIRECTION OUTPUT ;
    USE SIGNAL ;
    SHAPE ABUTMENT ;
    PORT
      LAYER M3 ;
      RECT 58.095 73.387 58.113 73.441 ;
    END
  END r0_rd_out[67]
  PIN r0_rd_out[68]
    DIRECTION OUTPUT ;
    USE SIGNAL ;
    SHAPE ABUTMENT ;
    PORT
      LAYER M3 ;
      RECT 58.959 73.387 58.977 73.441 ;
    END
  END r0_rd_out[68]
  PIN r0_rd_out[69]
    DIRECTION OUTPUT ;
    USE SIGNAL ;
    SHAPE ABUTMENT ;
    PORT
      LAYER M3 ;
      RECT 59.823 73.387 59.841 73.441 ;
    END
  END r0_rd_out[69]
  PIN r0_rd_out[70]
    DIRECTION OUTPUT ;
    USE SIGNAL ;
    SHAPE ABUTMENT ;
    PORT
      LAYER M3 ;
      RECT 60.687 73.387 60.705 73.441 ;
    END
  END r0_rd_out[70]
  PIN r0_rd_out[71]
    DIRECTION OUTPUT ;
    USE SIGNAL ;
    SHAPE ABUTMENT ;
    PORT
      LAYER M3 ;
      RECT 61.551 73.387 61.569 73.441 ;
    END
  END r0_rd_out[71]
  PIN r0_rd_out[72]
    DIRECTION OUTPUT ;
    USE SIGNAL ;
    SHAPE ABUTMENT ;
    PORT
      LAYER M3 ;
      RECT 62.415 73.387 62.433 73.441 ;
    END
  END r0_rd_out[72]
  PIN r0_rd_out[73]
    DIRECTION OUTPUT ;
    USE SIGNAL ;
    SHAPE ABUTMENT ;
    PORT
      LAYER M3 ;
      RECT 63.279 73.387 63.297 73.441 ;
    END
  END r0_rd_out[73]
  PIN r0_rd_out[74]
    DIRECTION OUTPUT ;
    USE SIGNAL ;
    SHAPE ABUTMENT ;
    PORT
      LAYER M3 ;
      RECT 64.143 73.387 64.161 73.441 ;
    END
  END r0_rd_out[74]
  PIN r0_rd_out[75]
    DIRECTION OUTPUT ;
    USE SIGNAL ;
    SHAPE ABUTMENT ;
    PORT
      LAYER M3 ;
      RECT 65.007 73.387 65.025 73.441 ;
    END
  END r0_rd_out[75]
  PIN r0_rd_out[76]
    DIRECTION OUTPUT ;
    USE SIGNAL ;
    SHAPE ABUTMENT ;
    PORT
      LAYER M3 ;
      RECT 65.871 73.387 65.889 73.441 ;
    END
  END r0_rd_out[76]
  PIN r0_rd_out[77]
    DIRECTION OUTPUT ;
    USE SIGNAL ;
    SHAPE ABUTMENT ;
    PORT
      LAYER M3 ;
      RECT 66.735 73.387 66.753 73.441 ;
    END
  END r0_rd_out[77]
  PIN r0_rd_out[78]
    DIRECTION OUTPUT ;
    USE SIGNAL ;
    SHAPE ABUTMENT ;
    PORT
      LAYER M3 ;
      RECT 67.599 73.387 67.617 73.441 ;
    END
  END r0_rd_out[78]
  PIN r0_rd_out[79]
    DIRECTION OUTPUT ;
    USE SIGNAL ;
    SHAPE ABUTMENT ;
    PORT
      LAYER M3 ;
      RECT 68.463 73.387 68.481 73.441 ;
    END
  END r0_rd_out[79]
  PIN r0_rd_out[80]
    DIRECTION OUTPUT ;
    USE SIGNAL ;
    SHAPE ABUTMENT ;
    PORT
      LAYER M3 ;
      RECT 69.327 73.387 69.345 73.441 ;
    END
  END r0_rd_out[80]
  PIN r0_rd_out[81]
    DIRECTION OUTPUT ;
    USE SIGNAL ;
    SHAPE ABUTMENT ;
    PORT
      LAYER M3 ;
      RECT 70.191 73.387 70.209 73.441 ;
    END
  END r0_rd_out[81]
  PIN r0_rd_out[82]
    DIRECTION OUTPUT ;
    USE SIGNAL ;
    SHAPE ABUTMENT ;
    PORT
      LAYER M3 ;
      RECT 71.055 73.387 71.073 73.441 ;
    END
  END r0_rd_out[82]
  PIN r0_rd_out[83]
    DIRECTION OUTPUT ;
    USE SIGNAL ;
    SHAPE ABUTMENT ;
    PORT
      LAYER M3 ;
      RECT 71.919 73.387 71.937 73.441 ;
    END
  END r0_rd_out[83]
  PIN r0_rd_out[84]
    DIRECTION OUTPUT ;
    USE SIGNAL ;
    SHAPE ABUTMENT ;
    PORT
      LAYER M3 ;
      RECT 72.783 73.387 72.801 73.441 ;
    END
  END r0_rd_out[84]
  PIN r0_rd_out[85]
    DIRECTION OUTPUT ;
    USE SIGNAL ;
    SHAPE ABUTMENT ;
    PORT
      LAYER M3 ;
      RECT 73.647 73.387 73.665 73.441 ;
    END
  END r0_rd_out[85]
  PIN r0_rd_out[86]
    DIRECTION OUTPUT ;
    USE SIGNAL ;
    SHAPE ABUTMENT ;
    PORT
      LAYER M3 ;
      RECT 74.511 73.387 74.529 73.441 ;
    END
  END r0_rd_out[86]
  PIN r0_rd_out[87]
    DIRECTION OUTPUT ;
    USE SIGNAL ;
    SHAPE ABUTMENT ;
    PORT
      LAYER M3 ;
      RECT 75.375 73.387 75.393 73.441 ;
    END
  END r0_rd_out[87]
  PIN r0_rd_out[88]
    DIRECTION OUTPUT ;
    USE SIGNAL ;
    SHAPE ABUTMENT ;
    PORT
      LAYER M3 ;
      RECT 76.239 73.387 76.257 73.441 ;
    END
  END r0_rd_out[88]
  PIN r0_rd_out[89]
    DIRECTION OUTPUT ;
    USE SIGNAL ;
    SHAPE ABUTMENT ;
    PORT
      LAYER M3 ;
      RECT 77.103 73.387 77.121 73.441 ;
    END
  END r0_rd_out[89]
  PIN r0_rd_out[90]
    DIRECTION OUTPUT ;
    USE SIGNAL ;
    SHAPE ABUTMENT ;
    PORT
      LAYER M3 ;
      RECT 77.967 73.387 77.985 73.441 ;
    END
  END r0_rd_out[90]
  PIN r0_rd_out[91]
    DIRECTION OUTPUT ;
    USE SIGNAL ;
    SHAPE ABUTMENT ;
    PORT
      LAYER M3 ;
      RECT 78.831 73.387 78.849 73.441 ;
    END
  END r0_rd_out[91]
  PIN r0_rd_out[92]
    DIRECTION OUTPUT ;
    USE SIGNAL ;
    SHAPE ABUTMENT ;
    PORT
      LAYER M3 ;
      RECT 79.695 73.387 79.713 73.441 ;
    END
  END r0_rd_out[92]
  PIN r0_rd_out[93]
    DIRECTION OUTPUT ;
    USE SIGNAL ;
    SHAPE ABUTMENT ;
    PORT
      LAYER M3 ;
      RECT 80.559 73.387 80.577 73.441 ;
    END
  END r0_rd_out[93]
  PIN r0_rd_out[94]
    DIRECTION OUTPUT ;
    USE SIGNAL ;
    SHAPE ABUTMENT ;
    PORT
      LAYER M3 ;
      RECT 81.423 73.387 81.441 73.441 ;
    END
  END r0_rd_out[94]
  PIN r0_rd_out[95]
    DIRECTION OUTPUT ;
    USE SIGNAL ;
    SHAPE ABUTMENT ;
    PORT
      LAYER M3 ;
      RECT 82.287 73.387 82.305 73.441 ;
    END
  END r0_rd_out[95]
  PIN r0_rd_out[96]
    DIRECTION OUTPUT ;
    USE SIGNAL ;
    SHAPE ABUTMENT ;
    PORT
      LAYER M3 ;
      RECT 83.151 73.387 83.169 73.441 ;
    END
  END r0_rd_out[96]
  PIN r0_rd_out[97]
    DIRECTION OUTPUT ;
    USE SIGNAL ;
    SHAPE ABUTMENT ;
    PORT
      LAYER M3 ;
      RECT 84.015 73.387 84.033 73.441 ;
    END
  END r0_rd_out[97]
  PIN r0_rd_out[98]
    DIRECTION OUTPUT ;
    USE SIGNAL ;
    SHAPE ABUTMENT ;
    PORT
      LAYER M3 ;
      RECT 84.879 73.387 84.897 73.441 ;
    END
  END r0_rd_out[98]
  PIN r0_rd_out[99]
    DIRECTION OUTPUT ;
    USE SIGNAL ;
    SHAPE ABUTMENT ;
    PORT
      LAYER M3 ;
      RECT 85.743 73.387 85.761 73.441 ;
    END
  END r0_rd_out[99]
  PIN r0_rd_out[100]
    DIRECTION OUTPUT ;
    USE SIGNAL ;
    SHAPE ABUTMENT ;
    PORT
      LAYER M3 ;
      RECT 86.607 73.387 86.625 73.441 ;
    END
  END r0_rd_out[100]
  PIN r0_rd_out[101]
    DIRECTION OUTPUT ;
    USE SIGNAL ;
    SHAPE ABUTMENT ;
    PORT
      LAYER M3 ;
      RECT 87.471 73.387 87.489 73.441 ;
    END
  END r0_rd_out[101]
  PIN r0_rd_out[102]
    DIRECTION OUTPUT ;
    USE SIGNAL ;
    SHAPE ABUTMENT ;
    PORT
      LAYER M3 ;
      RECT 88.335 73.387 88.353 73.441 ;
    END
  END r0_rd_out[102]
  PIN r0_rd_out[103]
    DIRECTION OUTPUT ;
    USE SIGNAL ;
    SHAPE ABUTMENT ;
    PORT
      LAYER M3 ;
      RECT 89.199 73.387 89.217 73.441 ;
    END
  END r0_rd_out[103]
  PIN r0_rd_out[104]
    DIRECTION OUTPUT ;
    USE SIGNAL ;
    SHAPE ABUTMENT ;
    PORT
      LAYER M3 ;
      RECT 90.063 73.387 90.081 73.441 ;
    END
  END r0_rd_out[104]
  PIN r0_rd_out[105]
    DIRECTION OUTPUT ;
    USE SIGNAL ;
    SHAPE ABUTMENT ;
    PORT
      LAYER M3 ;
      RECT 90.927 73.387 90.945 73.441 ;
    END
  END r0_rd_out[105]
  PIN r0_rd_out[106]
    DIRECTION OUTPUT ;
    USE SIGNAL ;
    SHAPE ABUTMENT ;
    PORT
      LAYER M3 ;
      RECT 91.791 73.387 91.809 73.441 ;
    END
  END r0_rd_out[106]
  PIN r0_rd_out[107]
    DIRECTION OUTPUT ;
    USE SIGNAL ;
    SHAPE ABUTMENT ;
    PORT
      LAYER M3 ;
      RECT 92.655 73.387 92.673 73.441 ;
    END
  END r0_rd_out[107]
  PIN r0_rd_out[108]
    DIRECTION OUTPUT ;
    USE SIGNAL ;
    SHAPE ABUTMENT ;
    PORT
      LAYER M3 ;
      RECT 93.519 73.387 93.537 73.441 ;
    END
  END r0_rd_out[108]
  PIN r0_rd_out[109]
    DIRECTION OUTPUT ;
    USE SIGNAL ;
    SHAPE ABUTMENT ;
    PORT
      LAYER M3 ;
      RECT 94.383 73.387 94.401 73.441 ;
    END
  END r0_rd_out[109]
  PIN r0_rd_out[110]
    DIRECTION OUTPUT ;
    USE SIGNAL ;
    SHAPE ABUTMENT ;
    PORT
      LAYER M3 ;
      RECT 95.247 73.387 95.265 73.441 ;
    END
  END r0_rd_out[110]
  PIN r0_rd_out[111]
    DIRECTION OUTPUT ;
    USE SIGNAL ;
    SHAPE ABUTMENT ;
    PORT
      LAYER M3 ;
      RECT 96.111 73.387 96.129 73.441 ;
    END
  END r0_rd_out[111]
  PIN r0_rd_out[112]
    DIRECTION OUTPUT ;
    USE SIGNAL ;
    SHAPE ABUTMENT ;
    PORT
      LAYER M3 ;
      RECT 96.975 73.387 96.993 73.441 ;
    END
  END r0_rd_out[112]
  PIN r0_rd_out[113]
    DIRECTION OUTPUT ;
    USE SIGNAL ;
    SHAPE ABUTMENT ;
    PORT
      LAYER M3 ;
      RECT 97.839 73.387 97.857 73.441 ;
    END
  END r0_rd_out[113]
  PIN r0_rd_out[114]
    DIRECTION OUTPUT ;
    USE SIGNAL ;
    SHAPE ABUTMENT ;
    PORT
      LAYER M3 ;
      RECT 98.703 73.387 98.721 73.441 ;
    END
  END r0_rd_out[114]
  PIN r0_rd_out[115]
    DIRECTION OUTPUT ;
    USE SIGNAL ;
    SHAPE ABUTMENT ;
    PORT
      LAYER M3 ;
      RECT 99.567 73.387 99.585 73.441 ;
    END
  END r0_rd_out[115]
  PIN r0_rd_out[116]
    DIRECTION OUTPUT ;
    USE SIGNAL ;
    SHAPE ABUTMENT ;
    PORT
      LAYER M3 ;
      RECT 100.431 73.387 100.449 73.441 ;
    END
  END r0_rd_out[116]
  PIN r0_rd_out[117]
    DIRECTION OUTPUT ;
    USE SIGNAL ;
    SHAPE ABUTMENT ;
    PORT
      LAYER M3 ;
      RECT 101.295 73.387 101.313 73.441 ;
    END
  END r0_rd_out[117]
  PIN r0_rd_out[118]
    DIRECTION OUTPUT ;
    USE SIGNAL ;
    SHAPE ABUTMENT ;
    PORT
      LAYER M3 ;
      RECT 102.159 73.387 102.177 73.441 ;
    END
  END r0_rd_out[118]
  PIN r0_rd_out[119]
    DIRECTION OUTPUT ;
    USE SIGNAL ;
    SHAPE ABUTMENT ;
    PORT
      LAYER M3 ;
      RECT 103.023 73.387 103.041 73.441 ;
    END
  END r0_rd_out[119]
  PIN r0_rd_out[120]
    DIRECTION OUTPUT ;
    USE SIGNAL ;
    SHAPE ABUTMENT ;
    PORT
      LAYER M3 ;
      RECT 103.887 73.387 103.905 73.441 ;
    END
  END r0_rd_out[120]
  PIN r0_rd_out[121]
    DIRECTION OUTPUT ;
    USE SIGNAL ;
    SHAPE ABUTMENT ;
    PORT
      LAYER M3 ;
      RECT 104.751 73.387 104.769 73.441 ;
    END
  END r0_rd_out[121]
  PIN r0_rd_out[122]
    DIRECTION OUTPUT ;
    USE SIGNAL ;
    SHAPE ABUTMENT ;
    PORT
      LAYER M3 ;
      RECT 105.615 73.387 105.633 73.441 ;
    END
  END r0_rd_out[122]
  PIN r0_rd_out[123]
    DIRECTION OUTPUT ;
    USE SIGNAL ;
    SHAPE ABUTMENT ;
    PORT
      LAYER M3 ;
      RECT 106.479 73.387 106.497 73.441 ;
    END
  END r0_rd_out[123]
  PIN r0_rd_out[124]
    DIRECTION OUTPUT ;
    USE SIGNAL ;
    SHAPE ABUTMENT ;
    PORT
      LAYER M3 ;
      RECT 107.343 73.387 107.361 73.441 ;
    END
  END r0_rd_out[124]
  PIN r0_rd_out[125]
    DIRECTION OUTPUT ;
    USE SIGNAL ;
    SHAPE ABUTMENT ;
    PORT
      LAYER M3 ;
      RECT 108.207 73.387 108.225 73.441 ;
    END
  END r0_rd_out[125]
  PIN r0_rd_out[126]
    DIRECTION OUTPUT ;
    USE SIGNAL ;
    SHAPE ABUTMENT ;
    PORT
      LAYER M3 ;
      RECT 109.071 73.387 109.089 73.441 ;
    END
  END r0_rd_out[126]
  PIN r0_rd_out[127]
    DIRECTION OUTPUT ;
    USE SIGNAL ;
    SHAPE ABUTMENT ;
    PORT
      LAYER M3 ;
      RECT 109.935 73.387 109.953 73.441 ;
    END
  END r0_rd_out[127]
  PIN r0_rd_out[128]
    DIRECTION OUTPUT ;
    USE SIGNAL ;
    SHAPE ABUTMENT ;
    PORT
      LAYER M3 ;
      RECT 110.799 73.387 110.817 73.441 ;
    END
  END r0_rd_out[128]
  PIN r0_rd_out[129]
    DIRECTION OUTPUT ;
    USE SIGNAL ;
    SHAPE ABUTMENT ;
    PORT
      LAYER M3 ;
      RECT 111.663 73.387 111.681 73.441 ;
    END
  END r0_rd_out[129]
  PIN rw0_addr_in[0]
    DIRECTION INPUT ;
    USE SIGNAL ;
    SHAPE ABUTMENT ;
    PORT
      LAYER M4 ;
      RECT 0.000 58.884 0.072 58.908 ;
    END
  END rw0_addr_in[0]
  PIN rw0_addr_in[1]
    DIRECTION INPUT ;
    USE SIGNAL ;
    SHAPE ABUTMENT ;
    PORT
      LAYER M4 ;
      RECT 0.000 60.660 0.072 60.684 ;
    END
  END rw0_addr_in[1]
  PIN rw0_addr_in[2]
    DIRECTION INPUT ;
    USE SIGNAL ;
    SHAPE ABUTMENT ;
    PORT
      LAYER M4 ;
      RECT 0.000 62.436 0.072 62.460 ;
    END
  END rw0_addr_in[2]
  PIN rw0_addr_in[3]
    DIRECTION INPUT ;
    USE SIGNAL ;
    SHAPE ABUTMENT ;
    PORT
      LAYER M4 ;
      RECT 0.000 64.212 0.072 64.236 ;
    END
  END rw0_addr_in[3]
  PIN rw0_addr_in[4]
    DIRECTION INPUT ;
    USE SIGNAL ;
    SHAPE ABUTMENT ;
    PORT
      LAYER M4 ;
      RECT 119.268 57.108 119.340 57.132 ;
    END
  END rw0_addr_in[4]
  PIN rw0_addr_in[5]
    DIRECTION INPUT ;
    USE SIGNAL ;
    SHAPE ABUTMENT ;
    PORT
      LAYER M4 ;
      RECT 119.268 58.884 119.340 58.908 ;
    END
  END rw0_addr_in[5]
  PIN rw0_addr_in[6]
    DIRECTION INPUT ;
    USE SIGNAL ;
    SHAPE ABUTMENT ;
    PORT
      LAYER M4 ;
      RECT 119.268 60.660 119.340 60.684 ;
    END
  END rw0_addr_in[6]
  PIN r0_addr_in[0]
    DIRECTION INPUT ;
    USE SIGNAL ;
    SHAPE ABUTMENT ;
    PORT
      LAYER M4 ;
      RECT 0.000 65.988 0.072 66.012 ;
    END
  END r0_addr_in[0]
  PIN r0_addr_in[1]
    DIRECTION INPUT ;
    USE SIGNAL ;
    SHAPE ABUTMENT ;
    PORT
      LAYER M4 ;
      RECT 0.000 67.764 0.072 67.788 ;
    END
  END r0_addr_in[1]
  PIN r0_addr_in[2]
    DIRECTION INPUT ;
    USE SIGNAL ;
    SHAPE ABUTMENT ;
    PORT
      LAYER M4 ;
      RECT 0.000 69.540 0.072 69.564 ;
    END
  END r0_addr_in[2]
  PIN r0_addr_in[3]
    DIRECTION INPUT ;
    USE SIGNAL ;
    SHAPE ABUTMENT ;
    PORT
      LAYER M4 ;
      RECT 0.000 71.316 0.072 71.340 ;
    END
  END r0_addr_in[3]
  PIN r0_addr_in[4]
    DIRECTION INPUT ;
    USE SIGNAL ;
    SHAPE ABUTMENT ;
    PORT
      LAYER M4 ;
      RECT 119.268 62.436 119.340 62.460 ;
    END
  END r0_addr_in[4]
  PIN r0_addr_in[5]
    DIRECTION INPUT ;
    USE SIGNAL ;
    SHAPE ABUTMENT ;
    PORT
      LAYER M4 ;
      RECT 119.268 64.212 119.340 64.236 ;
    END
  END r0_addr_in[5]
  PIN r0_addr_in[6]
    DIRECTION INPUT ;
    USE SIGNAL ;
    SHAPE ABUTMENT ;
    PORT
      LAYER M4 ;
      RECT 119.268 65.988 119.340 66.012 ;
    END
  END r0_addr_in[6]
  PIN rw0_we_in
    DIRECTION INPUT ;
    USE SIGNAL ;
    SHAPE ABUTMENT ;
    PORT
      LAYER M3 ;
      RECT 112.527 73.387 112.545 73.441 ;
    END
  END rw0_we_in
  PIN rw0_ce_in
    DIRECTION INPUT ;
    USE SIGNAL ;
    SHAPE ABUTMENT ;
    PORT
      LAYER M3 ;
      RECT 113.391 73.387 113.409 73.441 ;
    END
  END rw0_ce_in
  PIN rw0_clk
    DIRECTION INPUT ;
    USE SIGNAL ;
    SHAPE ABUTMENT ;
    PORT
      LAYER M3 ;
      RECT 114.255 73.387 114.273 73.441 ;
    END
  END rw0_clk
  PIN r0_ce_in
    DIRECTION INPUT ;
    USE SIGNAL ;
    SHAPE ABUTMENT ;
    PORT
      LAYER M3 ;
      RECT 115.119 73.387 115.137 73.441 ;
    END
  END r0_ce_in
  PIN r0_clk
    DIRECTION INPUT ;
    USE SIGNAL ;
    SHAPE ABUTMENT ;
    PORT
      LAYER M3 ;
      RECT 115.983 73.387 116.001 73.441 ;
    END
  END r0_clk
  PIN VSS
    DIRECTION INOUT ;
    USE GROUND ;
    PORT
      LAYER M4 ;
      RECT 0.216 0.240 119.124 0.336 ;
      RECT 0.216 1.008 119.124 1.104 ;
      RECT 0.216 1.776 119.124 1.872 ;
      RECT 0.216 2.544 119.124 2.640 ;
      RECT 0.216 3.312 119.124 3.408 ;
      RECT 0.216 4.080 119.124 4.176 ;
      RECT 0.216 4.848 119.124 4.944 ;
      RECT 0.216 5.616 119.124 5.712 ;
      RECT 0.216 6.384 119.124 6.480 ;
      RECT 0.216 7.152 119.124 7.248 ;
      RECT 0.216 7.920 119.124 8.016 ;
      RECT 0.216 8.688 119.124 8.784 ;
      RECT 0.216 9.456 119.124 9.552 ;
      RECT 0.216 10.224 119.124 10.320 ;
      RECT 0.216 10.992 119.124 11.088 ;
      RECT 0.216 11.760 119.124 11.856 ;
      RECT 0.216 12.528 119.124 12.624 ;
      RECT 0.216 13.296 119.124 13.392 ;
      RECT 0.216 14.064 119.124 14.160 ;
      RECT 0.216 14.832 119.124 14.928 ;
      RECT 0.216 15.600 119.124 15.696 ;
      RECT 0.216 16.368 119.124 16.464 ;
      RECT 0.216 17.136 119.124 17.232 ;
      RECT 0.216 17.904 119.124 18.000 ;
      RECT 0.216 18.672 119.124 18.768 ;
      RECT 0.216 19.440 119.124 19.536 ;
      RECT 0.216 20.208 119.124 20.304 ;
      RECT 0.216 20.976 119.124 21.072 ;
      RECT 0.216 21.744 119.124 21.840 ;
      RECT 0.216 22.512 119.124 22.608 ;
      RECT 0.216 23.280 119.124 23.376 ;
      RECT 0.216 24.048 119.124 24.144 ;
      RECT 0.216 24.816 119.124 24.912 ;
      RECT 0.216 25.584 119.124 25.680 ;
      RECT 0.216 26.352 119.124 26.448 ;
      RECT 0.216 27.120 119.124 27.216 ;
      RECT 0.216 27.888 119.124 27.984 ;
      RECT 0.216 28.656 119.124 28.752 ;
      RECT 0.216 29.424 119.124 29.520 ;
      RECT 0.216 30.192 119.124 30.288 ;
      RECT 0.216 30.960 119.124 31.056 ;
      RECT 0.216 31.728 119.124 31.824 ;
      RECT 0.216 32.496 119.124 32.592 ;
      RECT 0.216 33.264 119.124 33.360 ;
      RECT 0.216 34.032 119.124 34.128 ;
      RECT 0.216 34.800 119.124 34.896 ;
      RECT 0.216 35.568 119.124 35.664 ;
      RECT 0.216 36.336 119.124 36.432 ;
      RECT 0.216 37.104 119.124 37.200 ;
      RECT 0.216 37.872 119.124 37.968 ;
      RECT 0.216 38.640 119.124 38.736 ;
      RECT 0.216 39.408 119.124 39.504 ;
      RECT 0.216 40.176 119.124 40.272 ;
      RECT 0.216 40.944 119.124 41.040 ;
      RECT 0.216 41.712 119.124 41.808 ;
      RECT 0.216 42.480 119.124 42.576 ;
      RECT 0.216 43.248 119.124 43.344 ;
      RECT 0.216 44.016 119.124 44.112 ;
      RECT 0.216 44.784 119.124 44.880 ;
      RECT 0.216 45.552 119.124 45.648 ;
      RECT 0.216 46.320 119.124 46.416 ;
      RECT 0.216 47.088 119.124 47.184 ;
      RECT 0.216 47.856 119.124 47.952 ;
      RECT 0.216 48.624 119.124 48.720 ;
      RECT 0.216 49.392 119.124 49.488 ;
      RECT 0.216 50.160 119.124 50.256 ;
      RECT 0.216 50.928 119.124 51.024 ;
      RECT 0.216 51.696 119.124 51.792 ;
      RECT 0.216 52.464 119.124 52.560 ;
      RECT 0.216 53.232 119.124 53.328 ;
      RECT 0.216 54.000 119.124 54.096 ;
      RECT 0.216 54.768 119.124 54.864 ;
      RECT 0.216 55.536 119.124 55.632 ;
      RECT 0.216 56.304 119.124 56.400 ;
      RECT 0.216 57.072 119.124 57.168 ;
      RECT 0.216 57.840 119.124 57.936 ;
      RECT 0.216 58.608 119.124 58.704 ;
      RECT 0.216 59.376 119.124 59.472 ;
      RECT 0.216 60.144 119.124 60.240 ;
      RECT 0.216 60.912 119.124 61.008 ;
      RECT 0.216 61.680 119.124 61.776 ;
      RECT 0.216 62.448 119.124 62.544 ;
      RECT 0.216 63.216 119.124 63.312 ;
      RECT 0.216 63.984 119.124 64.080 ;
      RECT 0.216 64.752 119.124 64.848 ;
      RECT 0.216 65.520 119.124 65.616 ;
      RECT 0.216 66.288 119.124 66.384 ;
      RECT 0.216 67.056 119.124 67.152 ;
      RECT 0.216 67.824 119.124 67.920 ;
      RECT 0.216 68.592 119.124 68.688 ;
      RECT 0.216 69.360 119.124 69.456 ;
      RECT 0.216 70.128 119.124 70.224 ;
      RECT 0.216 70.896 119.124 70.992 ;
      RECT 0.216 71.664 119.124 71.760 ;
      RECT 0.216 72.432 119.124 72.528 ;
      RECT 0.216 73.200 119.124 73.296 ;
    END
  END VSS
  PIN VDD
    DIRECTION INOUT ;
    USE POWER ;
    PORT
      LAYER M4 ;
      RECT 0.216 0.624 119.124 0.720 ;
      RECT 0.216 1.392 119.124 1.488 ;
      RECT 0.216 2.160 119.124 2.256 ;
      RECT 0.216 2.928 119.124 3.024 ;
      RECT 0.216 3.696 119.124 3.792 ;
      RECT 0.216 4.464 119.124 4.560 ;
      RECT 0.216 5.232 119.124 5.328 ;
      RECT 0.216 6.000 119.124 6.096 ;
      RECT 0.216 6.768 119.124 6.864 ;
      RECT 0.216 7.536 119.124 7.632 ;
      RECT 0.216 8.304 119.124 8.400 ;
      RECT 0.216 9.072 119.124 9.168 ;
      RECT 0.216 9.840 119.124 9.936 ;
      RECT 0.216 10.608 119.124 10.704 ;
      RECT 0.216 11.376 119.124 11.472 ;
      RECT 0.216 12.144 119.124 12.240 ;
      RECT 0.216 12.912 119.124 13.008 ;
      RECT 0.216 13.680 119.124 13.776 ;
      RECT 0.216 14.448 119.124 14.544 ;
      RECT 0.216 15.216 119.124 15.312 ;
      RECT 0.216 15.984 119.124 16.080 ;
      RECT 0.216 16.752 119.124 16.848 ;
      RECT 0.216 17.520 119.124 17.616 ;
      RECT 0.216 18.288 119.124 18.384 ;
      RECT 0.216 19.056 119.124 19.152 ;
      RECT 0.216 19.824 119.124 19.920 ;
      RECT 0.216 20.592 119.124 20.688 ;
      RECT 0.216 21.360 119.124 21.456 ;
      RECT 0.216 22.128 119.124 22.224 ;
      RECT 0.216 22.896 119.124 22.992 ;
      RECT 0.216 23.664 119.124 23.760 ;
      RECT 0.216 24.432 119.124 24.528 ;
      RECT 0.216 25.200 119.124 25.296 ;
      RECT 0.216 25.968 119.124 26.064 ;
      RECT 0.216 26.736 119.124 26.832 ;
      RECT 0.216 27.504 119.124 27.600 ;
      RECT 0.216 28.272 119.124 28.368 ;
      RECT 0.216 29.040 119.124 29.136 ;
      RECT 0.216 29.808 119.124 29.904 ;
      RECT 0.216 30.576 119.124 30.672 ;
      RECT 0.216 31.344 119.124 31.440 ;
      RECT 0.216 32.112 119.124 32.208 ;
      RECT 0.216 32.880 119.124 32.976 ;
      RECT 0.216 33.648 119.124 33.744 ;
      RECT 0.216 34.416 119.124 34.512 ;
      RECT 0.216 35.184 119.124 35.280 ;
      RECT 0.216 35.952 119.124 36.048 ;
      RECT 0.216 36.720 119.124 36.816 ;
      RECT 0.216 37.488 119.124 37.584 ;
      RECT 0.216 38.256 119.124 38.352 ;
      RECT 0.216 39.024 119.124 39.120 ;
      RECT 0.216 39.792 119.124 39.888 ;
      RECT 0.216 40.560 119.124 40.656 ;
      RECT 0.216 41.328 119.124 41.424 ;
      RECT 0.216 42.096 119.124 42.192 ;
      RECT 0.216 42.864 119.124 42.960 ;
      RECT 0.216 43.632 119.124 43.728 ;
      RECT 0.216 44.400 119.124 44.496 ;
      RECT 0.216 45.168 119.124 45.264 ;
      RECT 0.216 45.936 119.124 46.032 ;
      RECT 0.216 46.704 119.124 46.800 ;
      RECT 0.216 47.472 119.124 47.568 ;
      RECT 0.216 48.240 119.124 48.336 ;
      RECT 0.216 49.008 119.124 49.104 ;
      RECT 0.216 49.776 119.124 49.872 ;
      RECT 0.216 50.544 119.124 50.640 ;
      RECT 0.216 51.312 119.124 51.408 ;
      RECT 0.216 52.080 119.124 52.176 ;
      RECT 0.216 52.848 119.124 52.944 ;
      RECT 0.216 53.616 119.124 53.712 ;
      RECT 0.216 54.384 119.124 54.480 ;
      RECT 0.216 55.152 119.124 55.248 ;
      RECT 0.216 55.920 119.124 56.016 ;
      RECT 0.216 56.688 119.124 56.784 ;
      RECT 0.216 57.456 119.124 57.552 ;
      RECT 0.216 58.224 119.124 58.320 ;
      RECT 0.216 58.992 119.124 59.088 ;
      RECT 0.216 59.760 119.124 59.856 ;
      RECT 0.216 60.528 119.124 60.624 ;
      RECT 0.216 61.296 119.124 61.392 ;
      RECT 0.216 62.064 119.124 62.160 ;
      RECT 0.216 62.832 119.124 62.928 ;
      RECT 0.216 63.600 119.124 63.696 ;
      RECT 0.216 64.368 119.124 64.464 ;
      RECT 0.216 65.136 119.124 65.232 ;
      RECT 0.216 65.904 119.124 66.000 ;
      RECT 0.216 66.672 119.124 66.768 ;
      RECT 0.216 67.440 119.124 67.536 ;
      RECT 0.216 68.208 119.124 68.304 ;
      RECT 0.216 68.976 119.124 69.072 ;
      RECT 0.216 69.744 119.124 69.840 ;
      RECT 0.216 70.512 119.124 70.608 ;
      RECT 0.216 71.280 119.124 71.376 ;
      RECT 0.216 72.048 119.124 72.144 ;
      RECT 0.216 72.816 119.124 72.912 ;
    END
  END VDD
  OBS
    LAYER M1 ;
    RECT 0 0 119.340 73.441 ;
    LAYER M2 ;
    RECT 0 0 119.340 73.441 ;
    LAYER M3 ;
    RECT 0 0 119.340 73.441 ;
    LAYER M4 ;
    RECT 0 0 119.340 73.441 ;
  END
END fakeram_1rw1r_130w128d_sram

END LIBRARY
